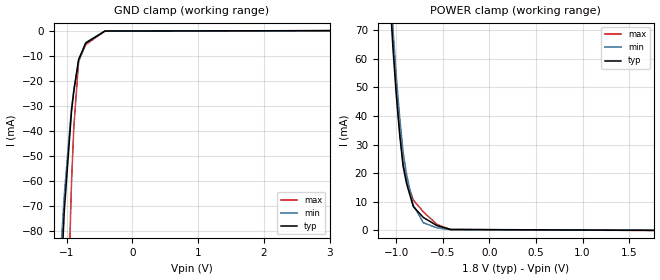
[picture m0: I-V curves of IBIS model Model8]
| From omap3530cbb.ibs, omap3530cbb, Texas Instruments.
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| Model based on original model for BQ0267CS_7LM
|   Sub model BQ0267CS_7LM_PU_ON_1P8
[model]   Model8
|[Input Load]   PU
|[Output Drive]
|Voltage   1.8V
|Mode   INPUT
Model_type   Input
Polarity   Non-Inverting
Vinl =  0.6615
Vinh =  1.2285
C_comp   1.666797p   1.351222p   1.845128p
[Model Spec]
Vinl   0.6615   0.6615   0.6615
Vinh   1.2285   1.2285   1.2285
[Temperature Range]   25   125   -40
[Voltage Range]   1.8   1.62   1.89
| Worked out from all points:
|   GND clamp passes 1 mA (typ) near -0.54 V on its own axis
|   POWER clamp passes 1 mA (typ) near -0.52 V on its own axis
[POWER_clamp]
-1.8V     610.1mA    624.3mA    666.8mA
-1.073V   84.13mA    90.54mA    90.67mA
-1.036V   63.78mA    70.41mA    67.93mA
-1V       47.17mA    53.82mA    49.6mA
-963.6mV  33.4mA     39.47mA    34.78mA
-927.3mV  22.45mA    27.38mA    23.45mA
-890.9mV  16.43mA    19.66mA    17.55mA
-818.2mV  8.267mA    8.667mA    10.56mA
-709.1mV  4.388mA    2.558mA    6.369mA
-563.6mV  1.554mA    772.7uA    1.972mA
-418.2mV  215.4uA    146.1uA    178uA
1.764V    -104.5uA   -51.64uA   -154uA
[GND_clamp]
-1.8V     -588mA     -437.3mA   -1.301A
-1.291V   -227.1mA   -178.9mA   -507.6mA
-1.255V   -202.5mA   -161.3mA   -452.9mA
-1.218V   -178.6mA   -144.2mA   -399.5mA
-1.182V   -155.1mA   -127.4mA   -347.1mA
-1.036V   -71.85mA   -65.55mA   -162.7mA
-927.3mV  -32.54mA   -31.18mA   -61.36mA
-890.9mV  -24.07mA   -23.7mA    -38.46mA
-818.2mV  -11.47mA   -12.29mA   -12.17mA
-709.1mV  -4.95mA    -4.761mA   -5.595mA
-418.2mV  -185.4uA   -235.3uA   -193.6uA
3.6V      0A         0A         0A
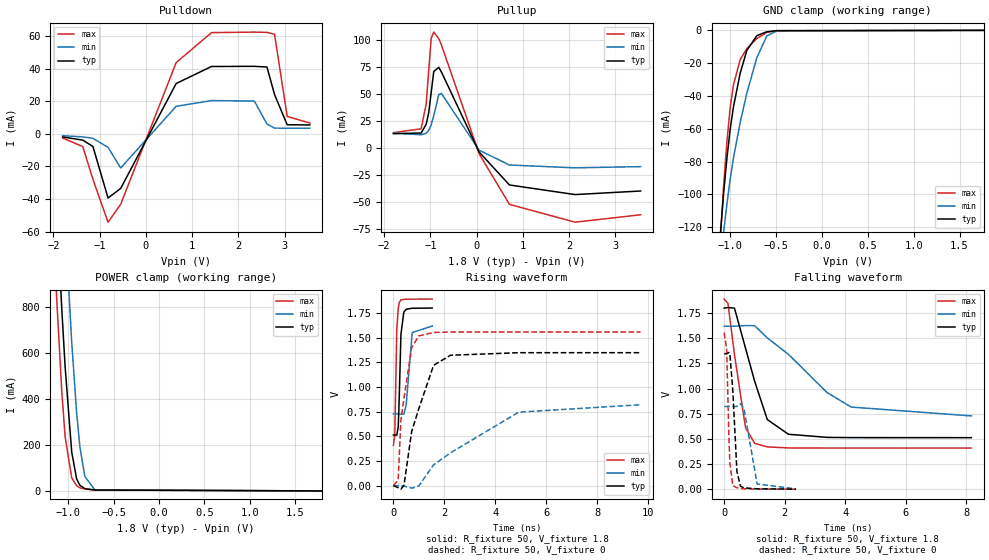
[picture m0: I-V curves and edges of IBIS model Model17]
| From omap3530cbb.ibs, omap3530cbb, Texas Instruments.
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| Model based on original model for BQ0253CS_7LM
|   Sub model BQ0253CS_7LM_PU_ON_1P8
[model]   Model17
|[Input Load]   PU
|[Output Drive]
|Voltage   1.8V
|Mode   I/O
Model_type   I/O
Polarity   Non-Inverting
Enable   Active-Low
Vinl =  0.63
Vinh =  1.17
Cref =  15.0000pF
Rref =  100.0000M
Vref =  0V
Vmeas =  0.9
C_comp   0.8825327p   0.7587673p   1.039339p
[Model Spec]
Vinl   0.63   0.567   0.6615
Vinh   1.17   1.053   1.2285
[Temperature Range]   25   125   -40
[Voltage Range]   1.8   1.62   1.89
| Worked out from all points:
|   slope of the pulldown table from 0 to 0.27 V, typ, clamps not added: 18.2 ohm
|   slope of the pullup table from 0 to 0.27 V, typ, clamps not added: 15.1 ohm
|   GND clamp passes 1 mA (typ) near -0.61 V on its own axis
|   POWER clamp passes 1 mA (typ) near -0.57 V on its own axis
|   rising waveform, R_fixture 50, V_fixture 1.8: 20-80 % time 80.7ps typ, 139ps min, 64.5ps max; typ from 0.513 V to 1.8 V
|   rising waveform, R_fixture 50, V_fixture 0: 20-80 % time 779ps typ, 2.51ns min, 382ps max; typ from 0.001 V to 1.35 V
|   falling waveform, R_fixture 50, V_fixture 1.8: 20-80 % time 756ps typ, 1.98ns min, 422ps max; typ from 1.8 V to 0.513 V
|   falling waveform, R_fixture 50, V_fixture 0: 20-80 % time 127ps typ, 249ps min, 81.5ps max; typ from 1.35 V to 0.002 V
[POWER_clamp]
-1.8V     7.03A      7.477A     6.772A
-1.182V   1.672A     2.34A      1.267A
-1.164V   1.518A     2.189A     1.114A
-1.127V   1.216A     1.889A     820.5mA
-1.073V   791.2mA    1.448A     431.2mA
-1.036V   538.2mA    1.164A     234.6mA
-963.6mV  169mA      647.7mA    57.34mA
-909.1mV  52.04mA    338.7mA    22.18mA
-872.7mV  24.24mA    189.9mA    13.43mA
-818.2mV  9.923mA    62.63mA    8.573mA
-709.1mV  3.896mA    5.034mA    3.819mA
1.8V      4.691nA    3.144nA    7.835nA
[Pulldown]
-1.8V     -1.896mA   -1.14mA    -2.549mA
-1.364V   -3.858mA   -1.868mA   -7.811mA
-1.145V   -7.758mA   -2.749mA   -27.9mA
-818.2mV  -39.37mA   -8.281mA   -54.21mA
-545.5mV  -33.5mA    -20.95mA   -43.25mA
654.5mV   30.89mA    16.9mA     43.69mA
1.418V    41.32mA    20.41mA    62.11mA
2.345V    41.43mA    20.12mA    62.44mA
2.618V    40.99mA    5.968mA    62.24mA
2.782V    24.07mA    3.525mA    61.09mA
3.055V    5.586mA    3.449mA    10.68mA
3.545V    5.467mA    3.446mA    6.63mA
[Pullup]
-1.8V     13mA       13.47mA    13.94mA
-1.2V     13.58mA    11.97mA    17.52mA
-1.091V   21.69mA    13.4mA     40.45mA
-1.036V   32.56mA    16.02mA    72.07mA
-981.8mV  51.55mA    21.35mA    101.5mA
-927.3mV  70.65mA    29.73mA    107.1mA
-818.2mV  74.4mA     49.19mA    101mA
-763.6mV  70.3mA     50.34mA    95.36mA
54.55mV   -4.056mA   -2.362mA   -5.695mA
709.1mV   -34.52mA   -16.04mA   -52.48mA
2.127V    -43.43mA   -18.65mA   -69.01mA
3.545V    -40.12mA   -17.52mA   -62.13mA
[GND_clamp]
-1.8V     -750.7mA   -623.3mA   -941.3mA
-1.109V   -125.7mA   -143.5mA   -129.9mA
-1.073V   -100.4mA   -123.9mA   -96.49mA
-1.036V   -78.3mA    -106.2mA   -68.25mA
-1V       -60.36mA   -90.76mA   -47.12mA
-963.6mV  -46.51mA   -77.61mA   -33.16mA
-890.9mV  -26.17mA   -56.18mA   -17.83mA
-818.2mV  -12.21mA   -38.34mA   -11.05mA
-709.1mV  -3.258mA   -16.62mA   -4.998mA
-600mV    -826.9uA   -3.389mA   -1.229mA
-490.9mV  -188.1uA   -312.3uA   -227.9uA
1.764V    -5.54uA    14.06uA    -26.2uA
[Ramp]
dV/dt_f  0.7815445/0.7631672n  0.5419933/2.008219n   0.9031261/0.4265498n
dV/dt_r  0.8331463/0.779493n   0.5086906/2.537851n   0.965152/0.3828609n
R_load = 50
[Rising Waveform]
R_fixture = 50
V_fixture = 1.8
V_fixture_min = 1.62
V_fixture_max = 1.89
0s        513.1mV    725.9mV    409.7mV
54ps      513.1mV    725.9mV    512.8mV
132ps     512.2mV    726.3mV    1.585V
190ps     595.1mV    726.5mV    1.791V
230ps     901.3mV    726.1mV    1.855V
296ps     1.533V     723.6mV    1.882V
408ps     1.756V     725.4mV    1.887V
500ps     1.787V     814.5mV    1.888V
738ps     1.797V     1.551V     1.889V
1.522ns   1.799V     1.617V     1.89V
[Rising Waveform]
R_fixture = 50
V_fixture = 0
V_fixture_min = 0
V_fixture_max = 0
0s        1.238mV    776.6uV    1.504mV
188ps     -19.74mV   915.1uV    59.45mV
294ps     -34.6mV    1.085mV    667.6mV
416ps     6.055mV    -4.004mV   885.6mV
716ps     547.3mV    -24.5mV    1.398V
996ps     779.5mV    -2.2mV     1.517V
1.576ns   1.219V     211.1mV    1.552V
2.238ns   1.321V     332.9mV    1.556V
4.914ns   1.347V     744.8mV    1.556V
9.702ns   1.347V     819.9mV    1.556V
[Falling Waveform]
R_fixture = 50
V_fixture = 1.8
V_fixture_min = 1.62
V_fixture_max = 1.89
0s        1.8V       1.62V      1.89V
126ps     1.806V     1.62V      1.846V
340ps     1.8V       1.62V      1.34V
706ps     1.402V     1.627V     612.1mV
1.008ns   1.073V     1.626V     457.3mV
1.426ns   693.1mV    1.504V     421.6mV
2.124ns   547mV      1.341V     411.2mV
3.402ns   516.1mV    961.5mV    409.7mV
4.2ns     513.8mV    817.1mV    409.7mV
8.174ns   513.1mV    729.2mV    409.7mV
[Falling Waveform]
R_fixture = 50
V_fixture = 0
V_fixture_min = 0
V_fixture_max = 0
0s        1.347V     823.1mV    1.556V
82ps      1.347V     823.1mV    1.396V
156ps     1.36V      822.5mV    517.3mV
188ps     1.349V     822.3mV    263.5mV
286ps     981.6mV    821.7mV    36.79mV
422ps     177mV      824.2mV    14.81mV
538ps     32.12mV    851mV      10.26mV
654ps     14.22mV    803.7mV    5.479mV
1.09ns    5.212mV    53.26mV    2.809mV
2.376ns   1.916mV    4.022mV    1.588mV
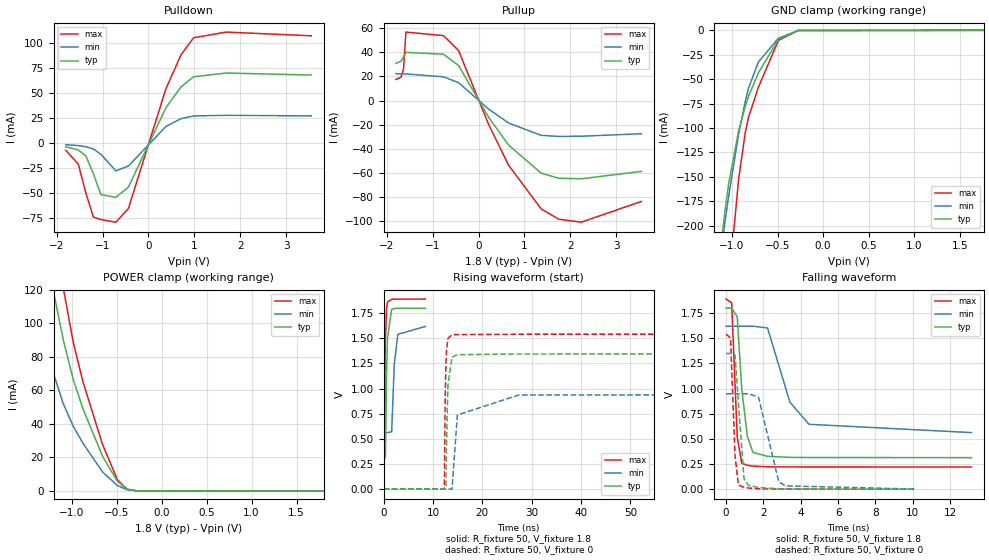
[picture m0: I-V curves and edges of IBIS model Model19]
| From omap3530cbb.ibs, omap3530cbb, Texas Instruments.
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| Model based on original model for BQ0447S_7LM
|   Sub model BQ0447S_7LM_OPEN_1P8
[model]   Model19
|[Input Load]   PI
|[Output Drive]
|Voltage   1.8V
|Mode   I/O
Model_type   I/O
Polarity   Non-Inverting
Enable   Active-Low
Vinl =  0.63
Vinh =  1.17
Cref =  15.0000pF
Rref =  100.0000M
Vref =  0V
Vmeas =  0.9
C_comp   14.35822p   13.74686p   15.2046p
[Model Spec]
Vinl   0.63   0.567   0.6615
Vinh   1.17   1.053   1.2285
[Temperature Range]   25   125   -40
[Voltage Range]   1.8   1.62   1.89
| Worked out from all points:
|   slope of the pulldown table from 0 to 0.27 V, typ, clamps not added: 10.4 ohm
|   slope of the pullup table from 0 to 0.27 V, typ, clamps not added: 16.1 ohm
|   GND clamp passes 1 mA (typ) near -0.34 V on its own axis
|   POWER clamp passes 1 mA (typ) near -0.38 V on its own axis
|   rising waveform, R_fixture 50, V_fixture 1.8: 20-80 % time 309ps typ, 590ps min, 201ps max; typ from 0.313 V to 1.8 V
|   rising waveform, R_fixture 50, V_fixture 0: 20-80 % time 387ps typ, 2ns min, 239ps max; typ from 0 V to 1.35 V
|   falling waveform, R_fixture 50, V_fixture 1.8: 20-80 % time 397ps typ, 1.15ns min, 221ps max; typ from 1.8 V to 0.314 V
|   falling waveform, R_fixture 50, V_fixture 0: 20-80 % time 255ps typ, 657ps min, 169ps max; typ from 1.35 V to 0 V
[POWER_clamp]
-1.8V     303.4mA    203.4mA    381.1mA
-1.455V   193.8mA    122.8mA    249.4mA
-1.218V   124mA      73.42mA    164.2mA
-1.2V     118.8mA    69.94mA    157.8mA
-1.091V   89.97mA    51.91mA    120.8mA
-981.8mV  66.58mA    38.67mA    88.78mA
-872.7mV  48.89mA    28.38mA    65mA
-654.5mV  20.58mA    11.27mA    27.57mA
-490.9mV  5.761mA    3.217mA    6.81mA
-381.8mV  1.056mA    692uA      943.7uA
-272.7mV  66.9uA     68.21uA    41.35uA
1.8V      41.6nA     285.5nA    43.96nA
[Pulldown]
-1.8V     -4.045mA   -1.989mA   -7.643mA
-1.527V   -7.297mA   -2.932mA   -21.5mA
-1.364V   -13.13mA   -4.035mA   -50.14mA
-1.2V     -30.92mA   -6.24mA    -74.18mA
-1.036V   -51.82mA   -11.63mA   -76.77mA
-709.1mV  -54.59mA   -28.19mA   -79.4mA
-436.4mV  -44.39mA   -23.3mA    -65.68mA
381.8mV   34.97mA    16.22mA    53.99mA
709.1mV   55.7mA     23.96mA    87.7mA
981.8mV   65.76mA    26.68mA    104.7mA
1.691V    69.52mA    27.31mA    110.4mA
3.545V    67.51mA    26.7mA     106.7mA
[Pullup]
-1.8V     30.85mA    22.33mA    17.55mA
-1.691V   32.55mA    22.17mA    19.38mA
-1.636V   35.97mA    22.14mA    25.89mA
-1.582V   40.02mA    22.12mA    56.78mA
-763.6mV  38.44mA    19.71mA    53.84mA
-436.4mV  29.17mA    14.9mA     41.51mA
218.2mV   -13.71mA   -6.987mA   -19.71mA
654.5mV   -36.87mA   -18.56mA   -53.56mA
1.364V    -60.07mA   -28.75mA   -89.7mA
1.745V    -64.29mA   -29.65mA   -98.22mA
2.236V    -64.75mA   -29.49mA   -100.7mA
3.545V    -58.6mA    -27.43mA   -83.51mA
[GND_clamp]
-1.8V     -901.6mA   -764.7mA   -1.495A
-1.218V   -303.4mA   -297.3mA   -491.3mA
-1.182V   -270.3mA   -270.3mA   -440.1mA
-1.073V   -181.9mA   -193.4mA   -303mA
-1.036V   -156.9mA   -169.4mA   -261mA
-927.3mV  -102.9mA   -106mA     -152.4mA
-854.5mV  -77.94mA   -72.99mA   -104.8mA
-818.2mV  -67.27mA   -58.97mA   -88.77mA
-709.1mV  -43.37mA   -32.32mA   -57.99mA
-490.9mV  -9.476mA   -8.137mA   -10.47mA
-272.7mV  -130.2uA   -230.7uA   -82.15uA
1.764V    38.64nA    3.228uA    40.69nA
[Ramp]
dV/dt_f  0.8932329/0.3927921n  0.6370527/1.142175n   1.003819/0.2201368n
dV/dt_r  0.8096603/0.3800384n  0.5693228/0.801983n   0.925524/0.2383233n
R_load = 50
[Rising Waveform]
R_fixture = 50
V_fixture = 1.8
V_fixture_min = 1.62
V_fixture_max = 1.89
0s        313.1mV    560.9mV    220.7mV
120ps     313.2mV    560.9mV    226mV
300ps     313.1mV    560.9mV    1.32V
360ps     325.6mV    560.9mV    1.496V
600ps     1.17V      560.9mV    1.804V
780ps     1.505V     561.3mV    1.86V
1.62ns    1.787V     570.8mV    1.888V
2.16ns    1.796V     1.245V     1.889V
2.88ns    1.798V     1.539V     1.889V
8.46ns    1.799V     1.618V     1.89V
[Rising Waveform]
R_fixture = 50
V_fixture = 0
V_fixture_min = 0
V_fixture_max = 0
0s        1.543uV    7.401uV    396.5nV
12.3ns    2.326uV    13.75uV    288.1uV
12.48ns   -202.4uV   2.405uV    919.6mV
12.6ns    6.814mV    378.7nV    1.212V
12.72ns   383.6mV    -312.2nV   1.363V
13.02ns   1.037V     -18.87nV   1.498V
13.86ns   1.312V     -464.2uV   1.535V
14.94ns   1.337V     737.2mV    1.537V
27.36ns   1.344V     935.8mV    1.54V
312.7ns   1.348V     947.2mV    1.542V
[Falling Waveform]
R_fixture = 50
V_fixture = 1.8
V_fixture_min = 1.62
V_fixture_max = 1.89
0s        1.8V       1.62V      1.89V
300ps     1.8V       1.62V      1.853V
600ps     1.713V     1.62V      516.8mV
840ps     998.3mV    1.62V      258.1mV
1.14ns    524.9mV    1.62V      237.8mV
1.44ns    365.5mV    1.62V      229.8mV
2.22ns    326.8mV    1.603V     222.7mV
3.42ns    316.4mV    864.5mV    221.3mV
4.44ns    314.7mV    645.1mV    221.1mV
13.14ns   313.5mV    562.5mV    220.8mV
[Falling Waveform]
R_fixture = 50
V_fixture = 0
V_fixture_min = 0
V_fixture_max = 0
0s        1.349V     948.8mV    1.542V
240ps     1.349V     948.8mV    1.502V
480ps     1.335V     948.8mV    335.9mV
660ps     865.2mV    948.8mV    41.54mV
960ps     106.4mV    948.8mV    18.6mV
1.2ns     37.13mV    948.8mV    11.53mV
1.74ns    16.21mV    915.2mV    3.72mV
2.82ns    3.973mV    74.69mV    761.3uV
3.18ns    2.678mV    32.99mV    597.1uV
10.08ns   456.3uV    1.645mV    168.5uV
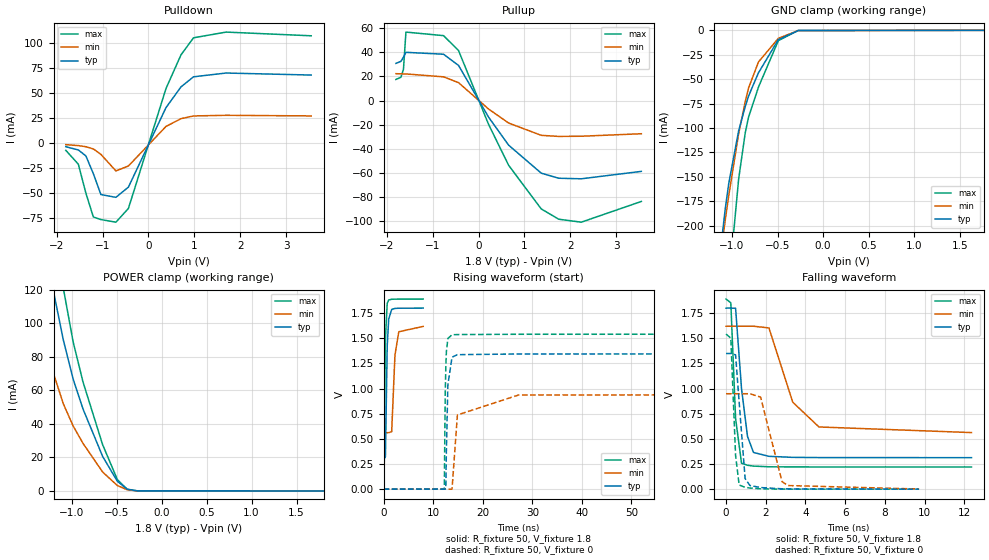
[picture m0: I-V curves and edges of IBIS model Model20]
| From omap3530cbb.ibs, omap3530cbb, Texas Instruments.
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| Model based on original model for BQ0447S_7LM
|   Sub model BQ0447S_7LM_PU_1P8
[model]   Model20
|[Input Load]   PU
|[Output Drive]
|Voltage   1.8V
|Mode   I/O
Model_type   I/O
Polarity   Non-Inverting
Enable   Active-Low
Vinl =  0.63
Vinh =  1.17
Cref =  15.0000pF
Rref =  100.0000M
Vref =  0V
Vmeas =  0.9
C_comp   14.35822p   13.74686p   15.2046p
[Model Spec]
Vinl   0.63   0.567   0.6615
Vinh   1.17   1.053   1.2285
[Temperature Range]   25   125   -40
[Voltage Range]   1.8   1.62   1.89
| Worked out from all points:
|   slope of the pulldown table from 0 to 0.27 V, typ, clamps not added: 10.4 ohm
|   slope of the pullup table from 0 to 0.27 V, typ, clamps not added: 16.1 ohm
|   GND clamp passes 1 mA (typ) near -0.34 V on its own axis
|   POWER clamp passes 1 mA (typ) near -0.38 V on its own axis
|   rising waveform, R_fixture 50, V_fixture 1.8: 20-80 % time 309ps typ, 590ps min, 201ps max; typ from 0.313 V to 1.8 V
|   rising waveform, R_fixture 50, V_fixture 0: 20-80 % time 387ps typ, 1.98ns min, 239ps max; typ from 0 V to 1.35 V
|   falling waveform, R_fixture 50, V_fixture 1.8: 20-80 % time 397ps typ, 1.15ns min, 221ps max; typ from 1.8 V to 0.314 V
|   falling waveform, R_fixture 50, V_fixture 0: 20-80 % time 255ps typ, 657ps min, 169ps max; typ from 1.35 V to 0.001 V
[POWER_clamp]
-1.8V     303.4mA    203.4mA    381.1mA
-1.455V   193.8mA    122.8mA    249.4mA
-1.218V   124mA      73.42mA    164.3mA
-1.2V     118.8mA    69.94mA    157.8mA
-1.091V   89.98mA    51.91mA    120.8mA
-981.8mV  66.59mA    38.68mA    88.78mA
-872.7mV  48.89mA    28.38mA    65.01mA
-654.5mV  20.58mA    11.28mA    27.58mA
-490.9mV  5.766mA    3.22mA     6.817mA
-381.8mV  1.06mA     694.7uA    950.1uA
-272.7mV  70.48uA    70.45uA    46.36uA
1.8V      41.6nA     285.5nA    43.96nA
[Pulldown]
-1.8V     -4.045mA   -1.989mA   -7.643mA
-1.527V   -7.297mA   -2.932mA   -21.5mA
-1.364V   -13.13mA   -4.035mA   -50.14mA
-1.2V     -30.92mA   -6.24mA    -74.18mA
-1.036V   -51.82mA   -11.63mA   -76.77mA
-709.1mV  -54.59mA   -28.19mA   -79.4mA
-436.4mV  -44.39mA   -23.3mA    -65.68mA
381.8mV   34.97mA    16.22mA    53.99mA
709.1mV   55.7mA     23.96mA    87.7mA
981.8mV   65.76mA    26.68mA    104.7mA
1.691V    69.52mA    27.31mA    110.4mA
3.545V    67.51mA    26.7mA     106.7mA
[Pullup]
-1.8V     30.85mA    22.33mA    17.55mA
-1.691V   32.55mA    22.17mA    19.38mA
-1.636V   35.97mA    22.14mA    25.89mA
-1.582V   40.02mA    22.12mA    56.78mA
-763.6mV  38.44mA    19.71mA    53.84mA
-436.4mV  29.17mA    14.9mA     41.51mA
218.2mV   -13.71mA   -6.987mA   -19.71mA
654.5mV   -36.87mA   -18.56mA   -53.56mA
1.364V    -60.07mA   -28.75mA   -89.7mA
1.745V    -64.29mA   -29.65mA   -98.22mA
2.236V    -64.75mA   -29.49mA   -100.7mA
3.545V    -58.6mA    -27.43mA   -83.51mA
[GND_clamp]
-1.8V     -901.6mA   -764.7mA   -1.495A
-1.218V   -303.4mA   -297.3mA   -491.3mA
-1.182V   -270.3mA   -270.3mA   -440.1mA
-1.073V   -181.9mA   -193.4mA   -303mA
-1.036V   -156.9mA   -169.4mA   -261mA
-927.3mV  -102.9mA   -106mA     -152.4mA
-854.5mV  -77.95mA   -73mA      -104.8mA
-818.2mV  -67.28mA   -58.97mA   -88.79mA
-709.1mV  -43.39mA   -32.33mA   -58.03mA
-490.9mV  -9.507mA   -8.155mA   -10.51mA
-272.7mV  -158.5uA   -247.6uA   -122.8uA
1.764V    -449.8nA   4.475uA    -2.299uA
[Ramp]
dV/dt_f  0.8931151/0.3926831n  0.6369209/1.141517n   1.003703/0.2200896n
dV/dt_r  0.8095912/0.3796781n  0.5692851/0.8011317n  0.9254441/0.2381167n
R_load = 50
[Rising Waveform]
R_fixture = 50
V_fixture = 1.8
V_fixture_min = 1.62
V_fixture_max = 1.89
0s        313.3mV    561.1mV    220.9mV
120ps     313.4mV    561.1mV    226.2mV
300ps     313.3mV    561.1mV    1.32V
360ps     325.8mV    561.1mV    1.497V
720ps     1.426V     561.3mV    1.848V
1.02ns    1.691V     561.8mV    1.881V
1.62ns    1.787V     571.1mV    1.888V
2.28ns    1.797V     1.333V     1.889V
3.06ns    1.799V     1.565V     1.89V
7.98ns    1.8V       1.618V     1.89V
[Rising Waveform]
R_fixture = 50
V_fixture = 0
V_fixture_min = 0
V_fixture_max = 0
0s        195.4uV    205.4uV    195.8uV
12.24ns   196.3uV    211.7uV    487.3uV
12.42ns   -7.22uV    200.4uV    919.9mV
12.54ns   7.055mV    198.4uV    1.213V
12.66ns   384mV      197.7uV    1.364V
12.96ns   1.037V     198.1uV    1.498V
13.8ns    1.312V     -256.4uV   1.535V
14.88ns   1.337V     737.5mV    1.537V
27.24ns   1.344V     936.2mV    1.54V
311.4ns   1.348V     947.3mV    1.542V
[Falling Waveform]
R_fixture = 50
V_fixture = 1.8
V_fixture_min = 1.62
V_fixture_max = 1.89
0s        1.8V       1.62V      1.89V
240ps     1.8V       1.62V      1.853V
480ps     1.799V     1.62V      703.3mV
780ps     998.3mV    1.62V      258.1mV
1.08ns    524.9mV    1.62V      237.8mV
1.38ns    365.5mV    1.62V      229.8mV
2.16ns    326.8mV    1.603V     222.7mV
3.36ns    316.4mV    864.5mV    221.4mV
4.68ns    314.5mV    618.6mV    221.2mV
12.36ns   313.6mV    562.8mV    221mV
[Falling Waveform]
R_fixture = 50
V_fixture = 0
V_fixture_min = 0
V_fixture_max = 0
0s        1.349V     948.9mV    1.542V
240ps     1.349V     948.9mV    1.502V
480ps     1.335V     948.9mV    336mV
660ps     865.3mV    948.9mV    41.58mV
960ps     106.4mV    948.9mV    18.64mV
1.2ns     37.18mV    949mV      11.57mV
1.74ns    16.26mV    915.3mV    3.756mV
2.82ns    4.019mV    74.83mV    809.8uV
3.12ns    2.894mV    36.22mV    671.9uV
9.72ns    531.6uV    1.851mV    321.7uV
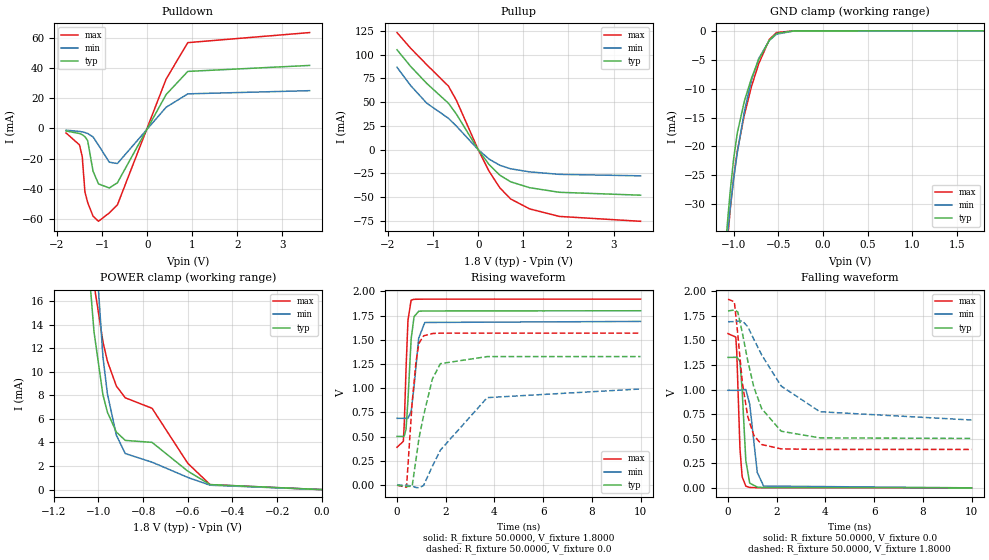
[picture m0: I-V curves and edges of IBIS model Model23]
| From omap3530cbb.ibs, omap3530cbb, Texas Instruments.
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| Model based on original model for DSIPHY_7LM
|   Sub model gpio_dx
[model]   Model23
|[Input Load]
|[Output Drive]
|Voltage   1.8000V
|Mode   I/O
Model_type I/O
Polarity   Non-Inverting
Enable   Active-High
Vinl =   0.4000V
Vinh =   1.4000V
Cref = 20pF
Rref = 10k
Vref = 0V
Vmeas =  0.9
C_comp   1.5000pF   1.4000pF   1.6000pF
[Temperature Range]   25.0000   0.1100k   -40.0000
[Voltage Range]   1.8000V   1.6900V   1.9200V
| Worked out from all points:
|   slope of the pulldown table from 0 to 0.27 V, typ, clamps not added: 17.9 ohm
|   slope of the pullup table from 0 to 0.27 V, typ, clamps not added: 15.7 ohm
|   GND clamp passes 1 mA (typ) near -0.57 V on its own axis
|   POWER clamp passes 1 mA (typ) near -0.56 V on its own axis
|   rising waveform, R_fixture 50.0000, V_fixture 1.8000: 20-80 % time 163ps typ, 221ps min, 126ps max; typ from 0.503 V to 1.8 V
|   rising waveform, R_fixture 50.0000, V_fixture 0.0: 20-80 % time 630ps typ, 1.6ns min, 293ps max; typ from 0 V to 1.33 V
|   falling waveform, R_fixture 50.0000, V_fixture 0.0: 20-80 % time 170ps typ, 253ps min, 133ps max; typ from 1.33 V to 0 V
|   falling waveform, R_fixture 50.0000, V_fixture 1.8000: 20-80 % time 854ps typ, 1.71ns min, 457ps max; typ from 1.8 V to 0.503 V
[Pulldown]
-1.8V     -1.734mA   -1.194mA   -3.023mA
-1.5V     -3.408mA   -2.016mA   -10.94mA
-1.44V    -4.211mA   -2.33mA    -18.71mA
-1.38V    -5.513mA   -2.754mA   -42.05mA
-1.32V    -8.079mA   -3.352mA   -48.98mA
-1.2V     -28.36mA   -5.657mA   -58.07mA
-1.08V    -36.71mA   -11.09mA   -61.44mA
-840mV    -39.42mA   -22.37mA   -55.89mA
-660mV    -35.96mA   -23.23mA   -50.58mA
420mV     22.37mA    13.96mA    32.59mA
900mV     37.65mA    22.81mA    56.68mA
3.6V      41.6mA     24.92mA    63.33mA
[Pullup]
-1.8V     105.2mA    86.79mA    123.3mA
-1.5V     87.8mA     67.64mA    106.9mA
-1.14V    69.72mA    48.95mA    89.46mA
-660mV    48.93mA    33.07mA    66.96mA
-480mV    37.21mA    24.7mA     51.68mA
0V        22.99pA    8.01pA     54.91pA
240mV     -15.57mA   -9.825mA   -22.62mA
480mV     -26.83mA   -16.42mA   -40.16mA
720mV     -33.8mA    -20.11mA   -51.88mA
1.14V     -40mA      -23.35mA   -62.31mA
1.8V      -44.84mA   -25.95mA   -70.25mA
3.6V      -47.9mA    -27.51mA   -75.38mA
[GND_clamp]
-1.8V     -216.5mA   -190.9mA   -249.2mA
-1.08V    -34.96mA   -36.72mA   -38.27mA
-1.04V    -27.87mA   -30.76mA   -31.13mA
-1V       -22.05mA   -25.57mA   -25.33mA
-960mV    -17.69mA   -21.1mA    -20.85mA
-880mV    -12.12mA   -13.91mA   -14.5mA
-800mV    -8.161mA   -8.492mA   -9.579mA
-720mV    -5.008mA   -4.788mA   -5.698mA
-600mV    -1.609mA   -1.645mA   -1.473mA
-520mV    -446.3uA   -578.6uA   -291.1uA
-320mV    -4.076uA   -10.07uA   -2.168uA
1.8V      482.7pA    75.41nA    410.7pA
[POWER_clamp]
-1.8V     3.651A     2.994A     4.508A
-1.06V    25.18mA    47.72mA    25.53mA
-1.04V    18.08mA    32.73mA    20.93mA
-1.02V    13.37mA    22.64mA    17.43mA
-980mV    8.037mA    11.24mA    12.54mA
-960mV    6.565mA    8.132mA    10.89mA
-920mV    4.881mA    4.616mA    8.785mA
-880mV    4.173mA    3.057mA    7.785mA
-760mV    4.006mA    2.326mA    6.898mA
-600mV    1.566mA    1.033mA    2.23mA
-500mV    425.7uA    372.5uA    422.6uA
0V        482.7pA    2.598nA    445.9pA
[Ramp]
dV/dt_r  0.7964/0.6301n   0.5955/1.6028n   0.9415/0.2930n
dV/dt_f  0.7783/0.8543n   0.5998/1.7093n   0.9175/0.4566n
R_load = 50.0000
[Rising Waveform]
R_fixture= 50.0000
V_fixture= 1.8000
V_fixture_min= 1.6900
V_fixture_max= 1.9200
0s        502.8mV    689.6mV    390.9mV
260.3ps   502.8mV    689.8mV    452.1mV
300.3ps   508mV      689.6mV    645.6mV
370.4ps   576.8mV    689mV      1.198V
450.5ps   881.7mV    691mV      1.704V
580.6ps   1.509V     760.8mV    1.91V
700.7ps   1.739V     1.018V     1.918V
890.9ps   1.795V     1.517V     1.919V
1.141ns   1.798V     1.679V     1.92V
10ns      1.8V       1.69V      1.92V
[Rising Waveform]
R_fixture= 50.0000
V_fixture= 0.0
V_fixture_min= 0.0
V_fixture_max= 0.0
0s        162.7nV    203.1nV    258.6nV
390.4ps   -13.48mV   93.09uV    -22.31mV
620.6ps   -12.01mV   -10.83mV   847.9mV
780.8ps   267.2mV    -24.52mV   1.275V
900.9ps   482.7mV    -28.13mV   1.464V
1.091ns   718.5mV    -3.95mV    1.541V
1.452ns   1.096V     195.1mV    1.565V
1.782ns   1.254V     361.7mV    1.569V
3.704ns   1.327V     903.4mV    1.569V
10ns      1.327V     992.5mV    1.569V
[Falling Waveform]
R_fixture= 50.0000
V_fixture= 0.0
V_fixture_min= 0.0
V_fixture_max= 0.0
0s        1.327V     992.4mV    1.569V
320.3ps   1.328V     992.3mV    1.534V
360.4ps   1.331V     992.2mV    1.374V
490.5ps   1.288V     992.6mV    401.2mV
580.6ps   991.1mV    996.4mV    113.9mV
730.7ps   278.8mV    1.001V     16.99mV
890.9ps   48.43mV    852.1mV    4.604mV
1.201ns   7.343mV    156.8mV    1.183mV
1.462ns   3.098mV    18.3mV     767.3uV
10ns      193.7nV    17.53uV    271.1nV
[Falling Waveform]
R_fixture= 50.0000
V_fixture= 1.8000
V_fixture_min= 1.6900
V_fixture_max= 1.9200
0s        1.8V       1.69V      1.92V
260.3ps   1.809V     1.691V     1.892V
400.4ps   1.79V      1.696V     1.564V
590.6ps   1.574V     1.698V     1.065V
810.8ps   1.293V     1.64V      724.2mV
1.061ns   1.024V     1.511V     534mV
1.381ns   806.8mV    1.353V     441mV
2.182ns   576.1mV    1.036V     396.5mV
3.774ns   508.4mV    774.3mV    391mV
10ns      502.9mV    690.3mV    390.9mV
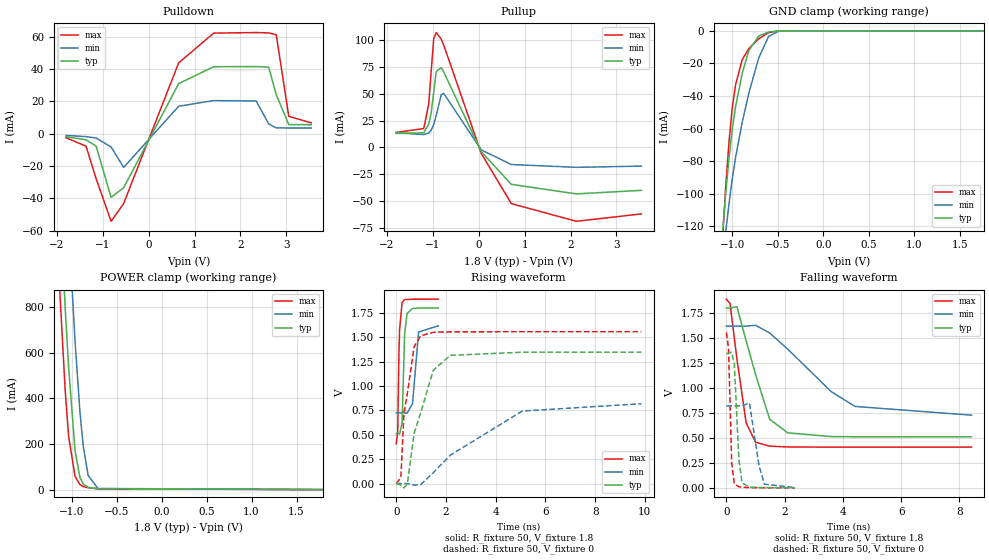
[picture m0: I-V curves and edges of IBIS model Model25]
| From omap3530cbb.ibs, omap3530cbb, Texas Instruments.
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| Model based on original model for BQ0230CS_7LM
|   Sub model 0230CS_PD_PU_OFF_1P8
[model]   Model25
|[Input Load]   PI
|[Output Drive]
|Voltage   1.8V
|Mode   I/O
Model_type   I/O
Polarity   Non-Inverting
Enable   Active-Low
Vinl =  0.63
Vinh =  1.17
Cref =  15.0000pF
Rref =  100.0000M
Vref =  0V
Vmeas =  0.9
C_comp   0.6926437p   0.6051649p   0.8002447p
[Model Spec]
Vinl   0.63   0.567   0.6615
Vinh   1.17   1.053   1.2285
[Temperature Range]   25   125   -40
[Voltage Range]   1.8   1.62   1.89
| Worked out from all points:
|   slope of the pulldown table from 0 to 0.27 V, typ, clamps not added: 18.2 ohm
|   slope of the pullup table from 0 to 0.27 V, typ, clamps not added: 15.1 ohm
|   GND clamp passes 1 mA (typ) near -0.62 V on its own axis
|   POWER clamp passes 1 mA (typ) near -0.57 V on its own axis
|   rising waveform, R_fixture 50, V_fixture 1.8: 20-80 % time 82.2ps typ, 143ps min, 65.7ps max; typ from 0.511 V to 1.8 V
|   rising waveform, R_fixture 50, V_fixture 0: 20-80 % time 779ps typ, 2.51ns min, 383ps max; typ from 0 V to 1.35 V
|   falling waveform, R_fixture 50, V_fixture 1.8: 20-80 % time 759ps typ, 1.98ns min, 424ps max; typ from 1.8 V to 0.511 V
|   falling waveform, R_fixture 50, V_fixture 0: 20-80 % time 127ps typ, 250ps min, 81.6ps max; typ from 1.35 V to 0.001 V
[POWER_clamp]
-1.8V     7.03A      7.477A     6.772A
-1.182V   1.672A     2.34A      1.267A
-1.164V   1.518A     2.189A     1.114A
-1.127V   1.216A     1.889A     820.4mA
-1.073V   791.2mA    1.448A     431.2mA
-1.036V   538.2mA    1.164A     234.5mA
-963.6mV  168.9mA    647.7mA    57.19mA
-909.1mV  51.95mA    338.6mA    22.02mA
-872.7mV  24.13mA    189.8mA    13.26mA
-818.2mV  9.807mA    62.59mA    8.409mA
-709.1mV  3.786mA    4.97mA     3.667mA
1.8V      5.595nA    3.536nA    9.29nA
[Pulldown]
-1.8V     -1.896mA   -1.14mA    -2.549mA
-1.364V   -3.858mA   -1.868mA   -7.811mA
-1.145V   -7.758mA   -2.749mA   -27.9mA
-818.2mV  -39.37mA   -8.28mA    -54.21mA
-545.5mV  -33.5mA    -20.95mA   -43.25mA
654.5mV   30.89mA    16.9mA     43.69mA
1.418V    41.32mA    20.41mA    62.11mA
2.345V    41.43mA    20.12mA    62.44mA
2.618V    40.99mA    5.968mA    62.24mA
2.782V    24.07mA    3.525mA    61.09mA
3.055V    5.586mA    3.449mA    10.68mA
3.545V    5.467mA    3.446mA    6.63mA
[Pullup]
-1.8V     13mA       13.47mA    13.94mA
-1.2V     13.58mA    11.97mA    17.52mA
-1.091V   21.69mA    13.4mA     40.44mA
-1.036V   32.56mA    16.02mA    72.05mA
-981.8mV  51.54mA    21.35mA    101.5mA
-927.3mV  70.65mA    29.72mA    107.1mA
-818.2mV  74.4mA     49.19mA    101mA
-763.6mV  70.3mA     50.34mA    95.36mA
54.55mV   -4.056mA   -2.362mA   -5.695mA
709.1mV   -34.52mA   -16.04mA   -52.48mA
2.127V    -43.43mA   -18.65mA   -69.01mA
3.545V    -40.12mA   -17.52mA   -62.13mA
[GND_clamp]
-1.8V     -750.6mA   -623.3mA   -941.3mA
-1.109V   -125.7mA   -143.5mA   -129.8mA
-1.073V   -100.3mA   -123.9mA   -96.46mA
-1.036V   -78.28mA   -106.2mA   -68.22mA
-1V       -60.33mA   -90.75mA   -47.08mA
-963.6mV  -46.48mA   -77.6mA    -33.12mA
-890.9mV  -26.13mA   -56.16mA   -17.76mA
-818.2mV  -12.14mA   -38.32mA   -10.94mA
-709.1mV  -3.178mA   -16.6mA    -4.875mA
-600mV    -741.1uA   -3.353mA   -1.097mA
-490.9mV  -93.82uA   -272.7uA   -81.21uA
1.764V    4.634nA    31.23nA    5.135nA
[Ramp]
dV/dt_f  0.7838245/0.7674859n  0.5431736/2.016907n   0.9061657/0.4292492n
dV/dt_r  0.8345672/0.7801617n  0.5086817/2.534964n   0.9673251/0.3833999n
R_load = 50
[Rising Waveform]
R_fixture = 50
V_fixture = 1.8
V_fixture_min = 1.62
V_fixture_max = 1.89
0s        511.5mV    724.7mV    407.9mV
60ps      511.3mV    724.7mV    531.4mV
108ps     510mV      724.8mV    1.321V
136ps     508.7mV    724.9mV    1.578V
236ps     618.3mV    724.9mV    1.854V
338ps     1.532V     723.9mV    1.885V
436ps     1.745V     721.3mV    1.887V
656ps     1.794V     818.7mV    1.889V
900ps     1.798V     1.553V     1.889V
1.696ns   1.799V     1.617V     1.89V
[Rising Waveform]
R_fixture = 50
V_fixture = 0
V_fixture_min = 0
V_fixture_max = 0
0s        196.5nV    87.63nV    427nV
188ps     -15.38mV   13.61uV    60.91mV
310ps     -44.05mV   178.9uV    718.9mV
450ps     -633.4uV   -16.84uV   925.9mV
720ps     514.1mV    -15.78mV   1.402V
980ps     722.8mV    -11.92mV   1.514V
1.49ns    1.161V     111.4mV    1.55V
2.18ns    1.314V     291.6mV    1.555V
5.07ns    1.346V     743mV      1.556V
9.858ns   1.346V     818.1mV    1.556V
[Falling Waveform]
R_fixture = 50
V_fixture = 1.8
V_fixture_min = 1.62
V_fixture_max = 1.89
0s        1.8V       1.62V      1.89V
126ps     1.801V     1.62V      1.847V
364ps     1.814V     1.62V      1.29V
680ps     1.473V     1.62V      651.7mV
1.004ns   1.135V     1.628V     456.9mV
1.488ns   687.2mV    1.551V     417.9mV
2.108ns   550.8mV    1.389V     409.6mV
3.596ns   513.8mV    964.4mV    407.9mV
4.416ns   512mV      815.5mV    407.9mV
8.414ns   511.5mV    727.9mV    407.9mV
[Falling Waveform]
R_fixture = 50
V_fixture = 0
V_fixture_min = 0
V_fixture_max = 0
0s        1.346V     821.4mV    1.556V
74ps      1.346V     821.5mV    1.405V
184ps     1.358V     820.9mV    248.3mV
274ps     1.241V     820.5mV    39.94mV
432ps     279.8mV    820.2mV    10.59mV
540ps     50.71mV    821.8mV    7.009mV
794ps     8.258mV    850.4mV    2.213mV
1.12ns    3.426mV    224.2mV    1.167mV
1.306ns   2.172mV    36.38mV    771.4uV
2.354ns   681.5uV    3.249mV    81.16uV
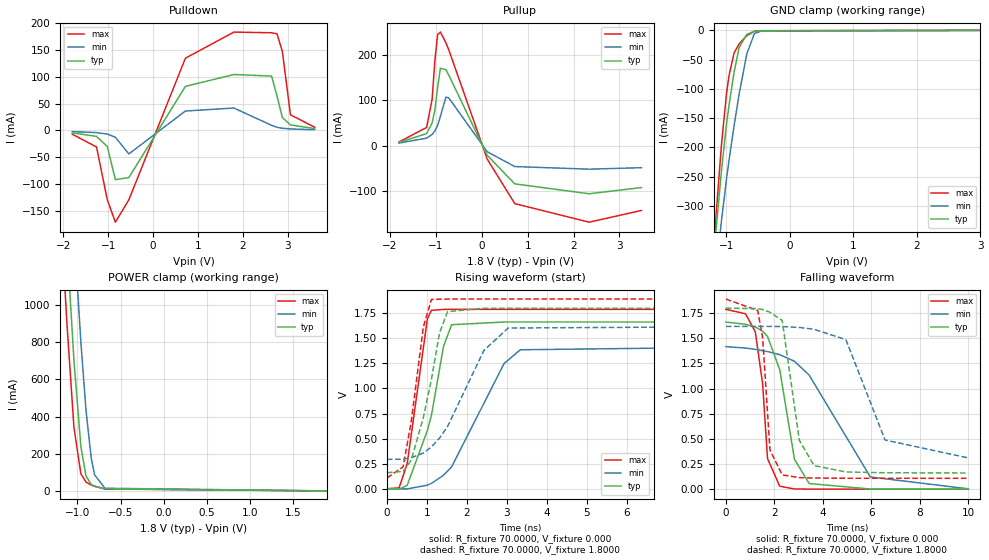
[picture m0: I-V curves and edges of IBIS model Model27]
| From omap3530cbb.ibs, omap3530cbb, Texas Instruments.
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| Model based on original model for BQ0246S_7LM
|   Sub model BQ0246S_7LM_NOM
[model]   Model27
|[Input Load]
|[Output Drive]
|Voltage   1.8000V
|Mode   I/O
Model_type   I/O
Polarity   Non-Inverting
Enable   Active-Low
Vinl =   0.6615V
Vinh =   1.0530V
Vmeas =   0.9000V
Cref =  15.0000pF
Rref =  70.0000
Vref =  0.000V
C_comp   27.0699pF   15.4565pF   39.2456pF
[Temperature Range]   25.0000   0.1250k   -40.0000
[Voltage Range]   1.8000V   1.6200V   1.8900V
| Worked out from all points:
|   slope of the pulldown table from 0 to 0.27 V, typ, clamps not added: 7.19 ohm
|   slope of the pullup table from 0 to 0.27 V, typ, clamps not added: 6.32 ohm
|   GND clamp passes 1 mA (typ) near -0.50 V on its own axis
|   POWER clamp passes 1 mA (typ) near -0.42 V on its own axis
|   rising waveform, R_fixture 70.0000, V_fixture 0.000: 20-80 % time 536ps typ, 1.05ns min, 366ps max; typ from 0.003 V to 1.66 V
|   rising waveform, R_fixture 70.0000, V_fixture 1.8000: 20-80 % time 503ps typ, 982ps min, 357ps max; typ from 0.162 V to 1.8 V
|   falling waveform, R_fixture 70.0000, V_fixture 0.000: 20-80 % time 746ps typ, 1.96ns min, 378ps max; typ from 1.66 V to 0.003 V
|   falling waveform, R_fixture 70.0000, V_fixture 1.8000: 20-80 % time 487ps typ, 1.12ns min, 284ps max; typ from 1.8 V to 0.162 V
[Pulldown]
-1.8V     -4.445mA   -2.126mA   -6.996mA
-1.26V    -11.04mA   -4.025mA   -30.71mA
-1.02V    -29.82mA   -6.736mA   -128.8mA
-840mV    -91.43mA   -12.6mA    -170.6mA
-540mV    -87.67mA   -43.72mA   -129mA
720mV     81.92mA    36.14mA    134.3mA
1.8V      104mA      41.7mA     182.9mA
2.64V     101.1mA    9.526mA    181.6mA
2.76V     64.23mA    5.807mA    179.9mA
2.88V     23.98mA    4.088mA    146.8mA
3.06V     10.27mA    2.794mA    29.14mA
3.6V      3.524mA    1.407mA    5.962mA
[Pullup]
-1.8V     7.604mA    6.269mA    8.75mA
-1.2V     27.23mA    17.12mA    40.67mA
-1.08V    50.58mA    25.44mA    102.7mA
-1.02V    79.05mA    32.97mA    188.3mA
-960mV    129.4mA    45.19mA    245mA
-900mV    170.8mA    65.19mA    250.2mA
-780mV    167.6mA    107mA      226.8mA
-720mV    156.1mA    105.8mA    211.9mA
120mV     -20.62mA   -12.72mA   -29.04mA
720mV     -83.38mA   -45.32mA   -126.8mA
2.34V     -105.1mA   -51.09mA   -167.6mA
3.48V     -91.45mA   -47.78mA   -141.8mA
[GND_clamp]
-1.8V     -1.222A    -1.152A    -1.363A
-1.2V     -387.2mA   -450.4mA   -371mA
-1.16V    -336.3mA   -407.6mA   -310.2mA
-1.08V    -241mA     -326.5mA   -197.1mA
-1V       -161.1mA   -254.5mA   -108.6mA
-960mV    -128mA     -222.2mA   -77.4mA
-880mV    -71.17mA   -162.8mA   -38.58mA
-800mV    -29.24mA   -108.5mA   -23mA
-680mV    -6.808mA   -40.29mA   -9.038mA
-560mV    -1.734mA   -5.52mA    -1.729mA
-440mV    -712.8uA   -867uA     -705.7uA
3.6V      0A         0A         0A
[POWER_clamp]
-1.8V     7.644A     8.363A     7.23A
-1.2V     2.005A     2.755A     1.56A
-1.18V    1.83A      2.579A     1.387A
-1.14V    1.487A     2.231A     1.051A
-1.12V    1.32A      2.059A     889.9mA
-1.04V    701.3mA    1.398A     341.4mA
-960mV    239.2mA    801mA      92.52mA
-900mV    79.9mA     431.2mA    47.25mA
-840mV    34.57mA    177mA      31.56mA
-800mV    24.75mA    85.38mA    25.1mA
-680mV    11.25mA    14.42mA    10.49mA
1.89V     0A         0A         0A
[Ramp]
dV/dt_r   0.9945/0.5312n   0.8467/1.0443n   1.0703/0.3627n
dV/dt_f   0.9812/0.4824n   0.7828/1.1180n   1.0669/0.2906n
R_load = 70.0000
[Rising Waveform]
R_fixture = 70.0000
V_fixture = 0.000
V_fixture_min = 0.000
V_fixture_max = 0.000
0s        2.514mV    4.296mV    1.746mV
303ps     -1.766mV   1.683mV    11.58mV
505.1ps   35.5mV     1.032mV    249.7mV
1.01ns    581.3mV    37.7mV     1.689V
1.111ns   730.1mV    55.93mV    1.776V
1.414ns   1.419V     136.3mV    1.785V
1.616ns   1.633V     220mV      1.786V
2.929ns   1.66V      1.248V     1.786V
3.333ns   1.66V      1.384V     1.786V
10ns      1.66V      1.415V     1.786V
[Rising Waveform]
R_fixture = 70.0000
V_fixture = 1.8000
V_fixture_min = 1.6200
V_fixture_max = 1.8900
0s        161.6mV    294.1mV    109.7mV
404ps     175mV      296.4mV    220.6mV
606.1ps   285.9mV    310.2mV    669.2mV
909.1ps   710.5mV    357.9mV    1.61V
1.111ns   1.089V     418.2mV    1.884V
1.313ns   1.55V      505.9mV    1.887V
1.515ns   1.763V     621.5mV    1.888V
2.424ns   1.797V     1.378V     1.888V
3.03ns    1.797V     1.6V       1.888V
10ns      1.797V     1.616V     1.888V
[Falling Waveform]
R_fixture = 70.0000
V_fixture = 0.000
V_fixture_min = 0.000
V_fixture_max = 0.000
0s        1.66V      1.416V     1.786V
808.1ps   1.638V     1.402V     1.742V
1.212ns   1.611V     1.389V     1.564V
1.515ns   1.569V     1.376V     1.048V
1.717ns   1.518V     1.367V     305.3mV
2.222ns   1.186V     1.336V     31mV
2.828ns   299.3mV    1.271V     3.702mV
3.434ns   57.85mV    1.134V     2.641mV
5.96ns    3.238mV    122.8mV    2.003mV
10ns      2.828mV    5.304mV    1.945mV
[Falling Waveform]
R_fixture = 70.0000
V_fixture = 1.8000
V_fixture_min = 1.6200
V_fixture_max = 1.8900
0s        1.798V     1.617V     1.888V
1.313ns   1.793V     1.617V     1.774V
1.515ns   1.784V     1.617V     1.506V
1.818ns   1.757V     1.617V     390mV
2.323ns   1.675V     1.615V     143.5mV
3.03ns    486mV      1.606V     116mV
3.636ns   236.3mV    1.588V     112.5mV
4.949ns   172.7mV    1.486V     110.5mV
6.566ns   164.9mV    489.6mV    110mV
10ns      162.2mV    311.9mV    109.9mV
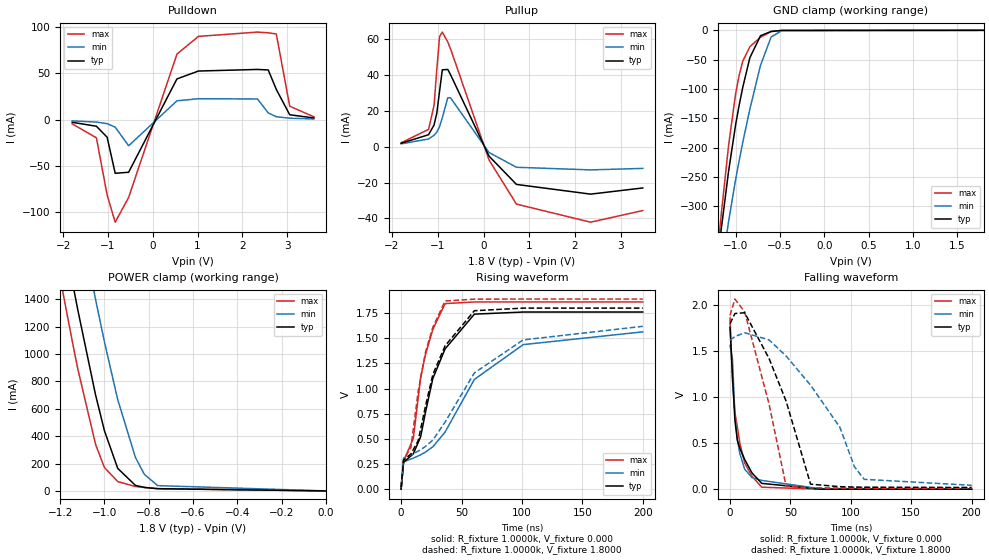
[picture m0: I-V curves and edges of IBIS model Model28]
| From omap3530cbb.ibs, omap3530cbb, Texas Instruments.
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| Model based on original model for BQ0246S_7LM
|   Sub model BQ0246S_7LM_I2C_2
[model]   Model28
|[Input Load]
|[Output Drive] HIGHC
|Voltage   1.8000V
|Mode   I/O
Model_type   I/O
Polarity   Non-Inverting
Enable   Active-Low
Vinl =   0.6615V
Vinh =   1.0530V
Vmeas =   0.9000V
Cref =  15.0000pF
Rref =  70.0000
Vref =  1.800V
C_comp   27.0699pF   15.4565pF   39.2456pF
[Temperature Range]   25.0000   0.1250k   -40.0000
[Voltage Range]   1.8000V   1.6200V   1.8900V
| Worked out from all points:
|   slope of the pulldown table from 0 to 0.27 V, typ, clamps not added: 11 ohm
|   slope of the pullup table from 0 to 0.27 V, typ, clamps not added: 25 ohm
|   GND clamp passes 1 mA (typ) near -0.56 V on its own axis
|   POWER clamp passes 1 mA (typ) near -0.50 V on its own axis
|   rising waveform, R_fixture 1.0000k, V_fixture 0.000: 20-80 % time 26.9ns typ, 65.3ns min, 16.2ns max; typ from 0 V to 1.76 V
|   rising waveform, R_fixture 1.0000k, V_fixture 1.8000: 20-80 % time 27.5ns typ, 66.1ns min, 16.4ns max; typ from 0.018 V to 1.8 V
|   falling waveform, R_fixture 1.0000k, V_fixture 0.000: 20-80 % time 9.81ns typ, 7.03ns min, 8.99ns max; typ from 1.76 V to 0 V
|   falling waveform, R_fixture 1.0000k, V_fixture 1.8000: 20-80 % time 28ns typ, 44.1ns min, 19.5ns max; typ from 1.8 V to 0.018 V
[Pulldown]
-1.8V     -2.87mA    -1.375mA   -4.529mA
-1.26V    -7.103mA   -2.596mA   -19.64mA
-1.02V    -19mA      -4.333mA   -81.54mA
-840mV    -58mA      -8.066mA   -110.9mA
-540mV    -56.9mA    -28.26mA   -84.16mA
540mV     44.06mA    20.37mA    70.88mA
1.02V     52.59mA    22.64mA    90.07mA
2.34V     54.31mA    22.37mA    94.71mA
2.58V     53.76mA    7.273mA    93.96mA
2.76V     32.74mA    3.19mA     92.69mA
3.06V     5.312mA    1.538mA    14.56mA
3.6V      1.833mA    776uA      3.052mA
[Pullup]
-1.8V     1.906mA    1.589mA    2.175mA
-1.2V     6.671mA    4.3mA      9.634mA
-1.08V    12.15mA    6.353mA    23.09mA
-1.02V    18.75mA    8.198mA    43.29mA
-960mV    31mA       11.19mA    61.33mA
-900mV    42.83mA    16.12mA    63.84mA
-780mV    43.01mA    27.29mA    58.27mA
-720mV    40.08mA    27.21mA    54.48mA
120mV     -5.231mA   -3.221mA   -7.396mA
720mV     -21.02mA   -11.47mA   -31.99mA
2.34V     -26.43mA   -12.93mA   -42.06mA
3.48V     -22.99mA   -12.1mA    -35.57mA
[GND_clamp]
-1.8V     -1.221A    -1.151A    -1.363A
-1.2V     -386.5mA   -449.7mA   -370.2mA
-1.16V    -335.5mA   -406.8mA   -309.4mA
-1.08V    -240.2mA   -325.8mA   -196.3mA
-1V       -160.3mA   -253.8mA   -107.7mA
-960mV    -127.1mA   -221.5mA   -76.33mA
-920mV    -97.28mA   -191.1mA   -52.71mA
-840mV    -46.78mA   -134.3mA   -27.94mA
-720mV    -9.253mA   -59.82mA   -11.79mA
-600mV    -1.888mA   -11.35mA   -2.27mA
-480mV    -137.6uA   -650.4uA   -84.11uA
1.8V      510.5nA    3.198uA    487.6nA
[POWER_clamp]
-1.8V     7.644A     8.363A     7.23A
-1.2V     2.004A     2.755A     1.56A
-1.18V    1.829A     2.578A     1.386A
-1.14V    1.486A     2.23A      1.05A
-1.12V    1.32A      2.059A     889mA
-1.04V    700.2mA    1.398A     339.6mA
-1V       439.3mA    1.088A     170.8mA
-940mV    164.6mA    666.7mA    68.12mA
-860mV    40.26mA    244.2mA    32.16mA
-820mV    25.74mA    121.5mA    25.05mA
-760mV    16.31mA    38.76mA    16.75mA
0V        510.5nA    462.5nA    537.3nA
[Ramp]
dV/dt_r   1.0568/26.6090n   0.9382/64.6276n   1.1166/15.9899n
dV/dt_f   1.0691/27.7433n   0.9467/45.2102n   1.1268/19.2673n
R_load = 1.0000k
[Rising Waveform]
R_fixture = 1.0000k
V_fixture = 0.000
V_fixture_min = 0.000
V_fixture_max = 0.000
0s        4.661uV    8.557uV    3.644uV
2.02ns    267.4mV    271.7mV    277.7mV
10.1ns    351.6mV    308.8mV    505.1mV
16.16ns   521.1mV    342mV      1.113V
20.2ns    767mV      369.2mV    1.341V
26.26ns   1.101V     421.8mV    1.589V
36.36ns   1.394V     567.6mV    1.845V
60.61ns   1.74V      1.091V     1.861V
101ns     1.761V     1.437V     1.861V
200ns     1.761V     1.564V     1.861V
[Rising Waveform]
R_fixture = 1.0000k
V_fixture = 1.8000
V_fixture_min = 1.6200
V_fixture_max = 1.8900
0s        17.75mV    32.74mV    11.97mV
2.02ns    288mV      309.1mV    291.7mV
8.081ns   348.6mV    341.3mV    414.2mV
14.14ns   483.4mV    378mV      974mV
20.2ns    827.5mV    424.6mV    1.364V
26.26ns   1.14V      488.1mV    1.609V
36.36ns   1.425V     666.4mV    1.871V
60.61ns   1.774V     1.156V     1.889V
101ns     1.8V       1.484V     1.89V
200ns     1.8V       1.619V     1.89V
[Falling Waveform]
R_fixture = 1.0000k
V_fixture = 0.000
V_fixture_min = 0.000
V_fixture_max = 0.000
0s        1.761V     1.564V     1.861V
2.02ns    1.239V     1.411V     1.186V
4.04ns    749.2mV    809.4mV    831.9mV
6.061ns   532.5mV    539.1mV    676.5mV
8.081ns   445.6mV    389.2mV    501.8mV
12.12ns   322.7mV    217.4mV    284.9mV
18.18ns   176.4mV    126.4mV    140.6mV
26.26ns   63.04mV    95.09mV    21.16mV
74.75ns   227.6uV    4.43mV     65.06uV
200ns     11.7uV     85.92uV    4.143uV
[Falling Waveform]
R_fixture = 1.0000k
V_fixture = 1.8000
V_fixture_min = 1.6200
V_fixture_max = 1.8900
0s        1.8V       1.62V      1.89V
4.04ns    1.911V     1.661V     2.068V
12.12ns   1.919V     1.701V     1.929V
32.32ns   1.421V     1.624V     925.4mV
46.46ns   955.7mV    1.448V     31.89mV
66.67ns   54.47mV    1.131V     14.94mV
90.91ns   26.84mV    673.8mV    12.69mV
103ns     22.93mV    242.9mV    12.34mV
111.1ns   21.66mV    106.9mV    12.23mV
200ns     18.14mV    42.11mV    11.98mV
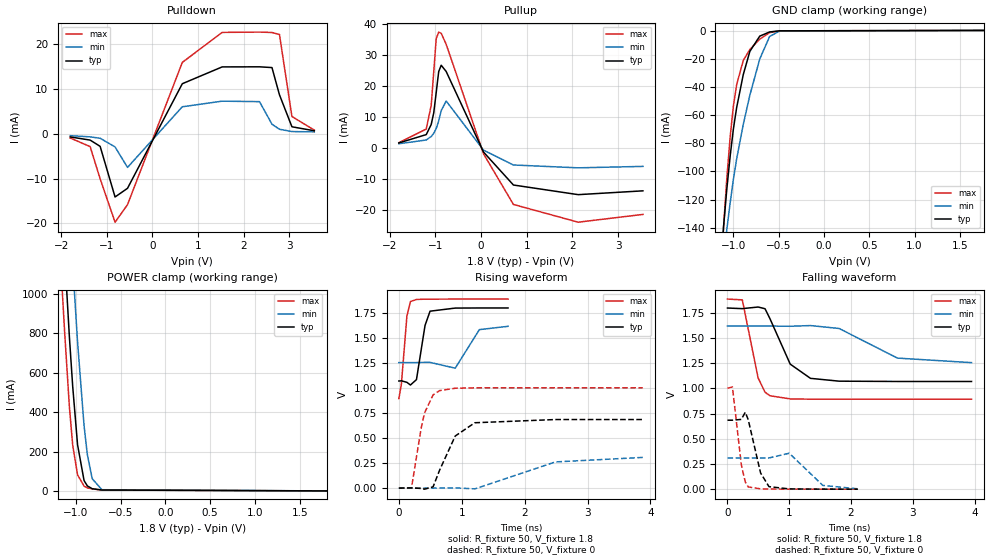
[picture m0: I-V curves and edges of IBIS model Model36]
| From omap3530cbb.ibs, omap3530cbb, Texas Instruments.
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| Model based on original model for BQOMAPPROGIOCSHYFBPB_7LM
|   Sub model MODE11_PD_ON_1P8
[model]   Model36
|[Input Load]   PD
|[Output Drive] DS11
|Voltage   1.8V
|Mode   I/O
Model_type   I/O
Polarity   Non-Inverting
Enable   Active-Low
Vinl =  0.63
Vinh =  1.17
Cref =  15.0000pF
Rref =  100.0000M
Vref =  0V
Vmeas =  0.9
C_comp   0.8864943p   0.7714798p   1.034566p
[Model Spec]
Vinl   0.63   0.567   0.6615
Vinh   1.17   1.053   1.2285
[Temperature Range]   25   125   -40
[Voltage Range]   1.8   1.62   1.89
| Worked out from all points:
|   slope of the pulldown table from 0 to 0.27 V, typ, clamps not added: 50.2 ohm
|   slope of the pullup table from 0 to 0.27 V, typ, clamps not added: 43.2 ohm
|   GND clamp passes 1 mA (typ) near -0.60 V on its own axis
|   POWER clamp passes 1 mA (typ) near -0.55 V on its own axis
|   rising waveform, R_fixture 50, V_fixture 1.8: 20-80 % time 108ps typ, 168ps min, 75.7ps max; typ from 1.07 V to 1.8 V
|   rising waveform, R_fixture 50, V_fixture 0: 20-80 % time 310ps typ, 715ps min, 175ps max; typ from 0 V to 0.684 V
|   falling waveform, R_fixture 50, V_fixture 1.8: 20-80 % time 338ps typ, 637ps min, 197ps max; typ from 1.8 V to 1.07 V
|   falling waveform, R_fixture 50, V_fixture 0: 20-80 % time 159ps typ, 301ps min, 108ps max; typ from 0.684 V to 0 V
[POWER_clamp]
-1.8V     7.429A     8.065A     7.064A
-1.182V   1.663A     2.35A      1.259A
-1.164V   1.508A     2.193A     1.106A
-1.127V   1.206A     1.883A     813.3mA
-1.073V   782.1mA    1.435A     426.3mA
-1.036V   530.7mA    1.15A      232.5mA
-981.8mV  234.7mA    756.3mA    81.79mA
-909.1mV  52.86mA    331.4mA    24.54mA
-872.7mV  25.66mA    185.5mA    15.5mA
-818.2mV  11.27mA    62mA       10.15mA
-709.1mV  4.611mA    6.166mA    4.556mA
1.8V      101uA      43.59uA    177.4uA
[Pulldown]
-1.8V     -685.7uA   -406.8uA   -929.8uA
-1.364V   -1.393mA   -666uA     -2.846mA
-1.145V   -2.793mA   -979uA     -10.06mA
-818.2mV  -14.12mA   -2.924mA   -19.76mA
-545.5mV  -12.18mA   -7.506mA   -15.84mA
654.5mV   11.22mA    6.067mA    15.99mA
1.527V    14.98mA    7.316mA    22.7mA
2.345V    15mA       7.209mA    22.77mA
2.618V    14.83mA    2.157mA    22.68mA
2.782V    8.739mA    1.031mA    22.24mA
3.055V    1.587mA    518.5uA    3.885mA
3.545V    690.3uA    442.8uA    842.1uA
[Pullup]
-1.8V     1.529mA    1.269mA    1.629mA
-1.2V     4.224mA    2.481mA    6.016mA
-1.091V   7.505mA    3.622mA    13.74mA
-1.036V   11.25mA    4.62mA     24.52mA
-981.8mV  17.83mA    6.179mA    35.2mA
-927.3mV  24.58mA    8.646mA    37.31mA
-872.7mV  26.61mA    11.97mA    36.93mA
-763.6mV  24.59mA    15.07mA    33.37mA
54.55mV   -1.419mA   -813.7uA   -1.994mA
709.1mV   -12.05mA   -5.587mA   -18.32mA
2.127V    -15.16mA   -6.505mA   -24.05mA
3.545V    -13.93mA   -6.04mA    -21.54mA
[GND_clamp]
-1.8V     -794.1mA   -670.5mA   -980.8mA
-1.109V   -139.6mA   -162.6mA   -140.1mA
-1.073V   -112.8mA   -141.5mA   -105.3mA
-1.036V   -89.25mA   -122.4mA   -75.78mA
-1V       -69.85mA   -105.6mA   -53.4mA
-963.6mV  -54.51mA   -90.99mA   -38.26mA
-890.9mV  -31.22mA   -66.62mA   -21.22mA
-818.2mV  -14.77mA   -45.88mA   -13.44mA
-709.1mV  -3.952mA   -20.19mA   -6.104mA
-600mV    -982.9uA   -4.198mA   -1.476mA
-490.9mV  -187.6uA   -374.7uA   -215.1uA
1.764V    101uA      43.71uA    177.3uA
[Ramp]
dV/dt_f  0.4432279/0.3387982n  0.2228411/0.6536895n  0.6043236/0.198385n
dV/dt_r  0.4197515/0.3104211n  0.1915724/0.7412433n  0.6120512/0.1755736n
R_load = 50
[Rising Waveform]
R_fixture = 50
V_fixture = 1.8
V_fixture_min = 1.62
V_fixture_max = 1.89
0s        1.069V     1.253V     892.8mV
40ps      1.071V     1.253V     1.037V
128ps     1.056V     1.253V     1.717V
184ps     1.029V     1.253V     1.862V
280ps     1.083V     1.253V     1.883V
416ps     1.623V     1.255V     1.886V
496ps     1.766V     1.255V     1.886V
896ps     1.797V     1.197V     1.887V
1.28ns    1.798V     1.582V     1.887V
1.736ns   1.798V     1.615V     1.887V
[Rising Waveform]
R_fixture = 50
V_fixture = 0
V_fixture_min = 0
V_fixture_max = 0
0s        443.1nV    254.2nV    1.018uV
200ps     2.658mV    4.996uV    -1.265mV
352ps     -3.306mV   -17.1uV    590.4mV
408ps     -10.49mV   -112.7uV   749.9mV
544ps     12.59mV    -66.89uV   930.3mV
648ps     179.5mV    595.1uV    973.4mV
896ps     519.9mV    2.326mV    996.8mV
1.208ns   652.5mV    -7.743mV   1.001V
2.488ns   684.4mV    261.4mV    1.001V
3.88ns    684.4mV    306.5mV    1.001V
[Falling Waveform]
R_fixture = 50
V_fixture = 1.8
V_fixture_min = 1.62
V_fixture_max = 1.89
0s        1.798V     1.619V     1.887V
240ps     1.792V     1.619V     1.879V
496ps     1.808V     1.619V     1.104V
608ps     1.791V     1.619V     962.4mV
688ps     1.692V     1.619V     927.4mV
1.016ns   1.241V     1.617V     895.9mV
1.344ns   1.1V       1.624V     893.2mV
1.808ns   1.072V     1.595V     892.9mV
2.752ns   1.069V     1.301V     892.9mV
3.952ns   1.069V     1.256V     892.9mV
[Falling Waveform]
R_fixture = 50
V_fixture = 0
V_fixture_min = 0
V_fixture_max = 0
0s        684.4mV    309.9mV    1.001V
80ps      684.5mV    309.9mV    1.015V
224ps     692.5mV    309.9mV    243mV
288ps     763.2mV    309.9mV    71.42mV
336ps     689.8mV    309.9mV    22.47mV
536ps     160.9mV    309.9mV    3.049mV
672ps     24.91mV    309.9mV    1.199mV
1ns       2.59mV     356.5mV    113.2uV
1.544ns   194.2uV    37.33mV    3.891uV
2.112ns   20.04uV    3.285mV    1.303uV
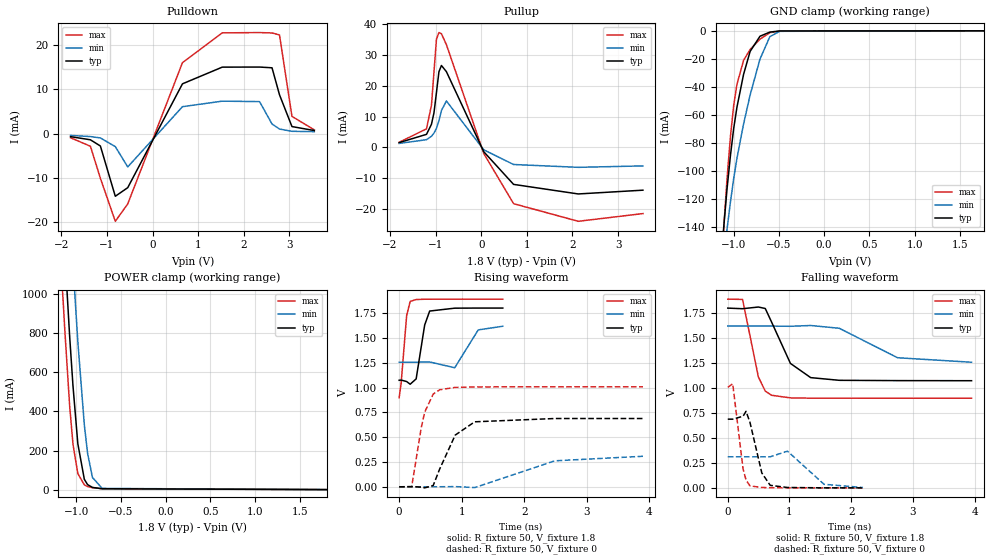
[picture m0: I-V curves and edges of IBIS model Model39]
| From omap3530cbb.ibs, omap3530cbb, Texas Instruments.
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| Model based on original model for BQOMAPPROGIOCSHYFBPB_7LM
|   Sub model MODE11_PU_PD_OFF_1P8
[model]   Model39
|[Input Load]   PI
|[Output Drive] DS11
|Voltage   1.8V
|Mode   I/O
Model_type   I/O
Polarity   Non-Inverting
Enable   Active-Low
Vinl =  0.63
Vinh =  1.17
Cref =  15.0000pF
Rref =  100.0000M
Vref =  0V
Vmeas =  0.9
C_comp   0.8864943p   0.7714798p   1.034566p
[Model Spec]
Vinl   0.63   0.567   0.6615
Vinh   1.17   1.053   1.2285
[Temperature Range]   25   125   -40
[Voltage Range]   1.8   1.62   1.89
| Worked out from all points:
|   slope of the pulldown table from 0 to 0.27 V, typ, clamps not added: 50.2 ohm
|   slope of the pullup table from 0 to 0.27 V, typ, clamps not added: 43.2 ohm
|   GND clamp passes 1 mA (typ) near -0.61 V on its own axis
|   POWER clamp passes 1 mA (typ) near -0.56 V on its own axis
|   rising waveform, R_fixture 50, V_fixture 1.8: 20-80 % time 107ps typ, 167ps min, 75.2ps max; typ from 1.07 V to 1.8 V
|   rising waveform, R_fixture 50, V_fixture 0: 20-80 % time 312ps typ, 718ps min, 176ps max; typ from 0 V to 0.688 V
|   falling waveform, R_fixture 50, V_fixture 1.8: 20-80 % time 338ps typ, 636ps min, 198ps max; typ from 1.8 V to 1.07 V
|   falling waveform, R_fixture 50, V_fixture 0: 20-80 % time 160ps typ, 303ps min, 109ps max; typ from 0.688 V to 0 V
[POWER_clamp]
-1.8V     7.429A     8.065A     7.064A
-1.182V   1.663A     2.35A      1.259A
-1.164V   1.508A     2.193A     1.106A
-1.127V   1.206A     1.883A     813.2mA
-1.073V   782.1mA    1.435A     426.3mA
-1.036V   530.6mA    1.15A      232.4mA
-981.8mV  234.7mA    756.3mA    81.67mA
-909.1mV  52.8mA     331.4mA    24.39mA
-872.7mV  25.58mA    185.5mA    15.34mA
-818.2mV  11.18mA    61.99mA    9.987mA
-709.1mV  4.516mA    6.134mA    4.387mA
1.8V      470.6pA    2.239nA    626.3pA
[Pulldown]
-1.8V     -685.7uA   -406.8uA   -929.8uA
-1.364V   -1.393mA   -666uA     -2.846mA
-1.145V   -2.793mA   -979uA     -10.06mA
-818.2mV  -14.12mA   -2.924mA   -19.76mA
-545.5mV  -12.18mA   -7.506mA   -15.84mA
654.5mV   11.22mA    6.067mA    15.99mA
1.527V    14.98mA    7.316mA    22.7mA
2.345V    15mA       7.209mA    22.77mA
2.618V    14.83mA    2.157mA    22.68mA
2.782V    8.738mA    1.031mA    22.24mA
3.055V    1.587mA    518.5uA    3.885mA
3.545V    690.3uA    442.8uA    842.1uA
[Pullup]
-1.8V     1.529mA    1.269mA    1.629mA
-1.2V     4.224mA    2.481mA    6.016mA
-1.091V   7.504mA    3.622mA    13.74mA
-1.036V   11.25mA    4.62mA     24.52mA
-981.8mV  17.82mA    6.179mA    35.19mA
-927.3mV  24.58mA    8.646mA    37.31mA
-872.7mV  26.61mA    11.97mA    36.93mA
-763.6mV  24.59mA    15.07mA    33.37mA
54.55mV   -1.419mA   -813.6uA   -1.993mA
709.1mV   -12.05mA   -5.587mA   -18.32mA
2.127V    -15.16mA   -6.504mA   -24.05mA
3.545V    -13.93mA   -6.04mA    -21.54mA
[GND_clamp]
-1.8V     -794.1mA   -670.5mA   -980.8mA
-1.109V   -139.6mA   -162.5mA   -140mA
-1.073V   -112.7mA   -141.5mA   -105.3mA
-1.036V   -89.23mA   -122.4mA   -75.75mA
-1V       -69.83mA   -105.6mA   -53.36mA
-963.6mV  -54.49mA   -90.99mA   -38.21mA
-890.9mV  -31.19mA   -66.62mA   -21.14mA
-818.2mV  -14.71mA   -45.88mA   -13.31mA
-709.1mV  -3.87mA    -20.18mA   -5.973mA
-600mV    -903.1uA   -4.176mA   -1.354mA
-490.9mV  -116.3uA   -342.2uA   -105.5uA
1.764V    389.6pA    119.4nA    561.5pA
[Ramp]
dV/dt_f  0.4425488/0.3390115n  0.2223979/0.6529139n  0.6048573/0.1989728n
dV/dt_r  0.4218333/0.3124462n  0.1921807/0.7437925n  0.6155477/0.1770175n
R_load = 50
[Rising Waveform]
R_fixture = 50
V_fixture = 1.8
V_fixture_min = 1.62
V_fixture_max = 1.89
0s        1.073V     1.255V     897.5mV
32ps      1.075V     1.255V     1.043V
120ps     1.06V      1.255V     1.725V
176ps     1.033V     1.255V     1.867V
272ps     1.087V     1.255V     1.886V
408ps     1.629V     1.257V     1.889V
488ps     1.77V      1.257V     1.889V
888ps     1.799V     1.199V     1.89V
1.264ns   1.8V       1.58V      1.89V
1.656ns   1.8V       1.617V     1.89V
[Rising Waveform]
R_fixture = 50
V_fixture = 0
V_fixture_min = 0
V_fixture_max = 0
0s        443.5nV    254.2nV    1.02uV
200ps     2.658mV    4.996uV    -1.27mV
352ps     -3.303mV   -17.1uV    590.8mV
408ps     -10.49mV   -112.7uV   751.1mV
544ps     12.58mV    -66.91uV   933.4mV
648ps     179.4mV    595.1uV    977.5mV
896ps     520.7mV    2.326mV    1.001V
1.208ns   654.7mV    -7.742mV   1.006V
2.488ns   687.8mV    261.8mV    1.007V
3.896ns   687.9mV    307.6mV    1.007V
[Falling Waveform]
R_fixture = 50
V_fixture = 1.8
V_fixture_min = 1.62
V_fixture_max = 1.89
0s        1.8V       1.62V      1.89V
240ps     1.794V     1.62V      1.887V
496ps     1.811V     1.62V      1.111V
608ps     1.796V     1.62V      968.7mV
712ps     1.658V     1.62V      927mV
1.016ns   1.246V     1.618V     901mV
1.344ns   1.104V     1.626V     898.2mV
1.808ns   1.077V     1.598V     897.7mV
2.752ns   1.074V     1.303V     897.6mV
3.952ns   1.073V     1.258V     897.5mV
[Falling Waveform]
R_fixture = 50
V_fixture = 0
V_fixture_min = 0
V_fixture_max = 0
0s        687.9mV    310.9mV    1.007V
80ps      687.9mV    310.9mV    1.043V
248ps     717mV      310.9mV    189.5mV
296ps     766.5mV    310.9mV    79.03mV
360ps     656.2mV    310.9mV    19.71mV
552ps     149.3mV    310.9mV    3.908mV
688ps     25.23mV    310.9mV    1.589mV
968ps     3.717mV    367.6mV    249.8uV
1.56ns    248.8uV    35.99mV    7.4uV
2.192ns   25.33uV    3.303mV    1.275uV
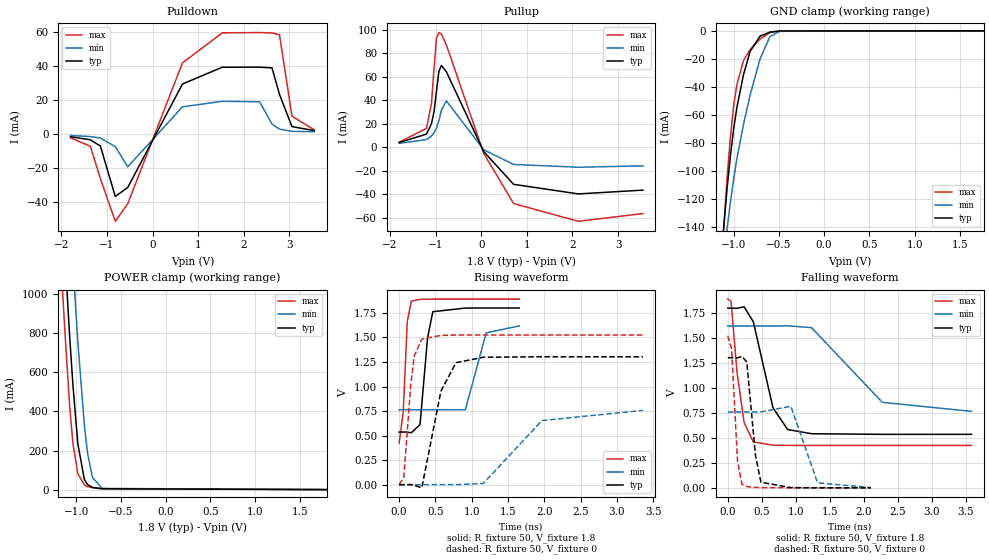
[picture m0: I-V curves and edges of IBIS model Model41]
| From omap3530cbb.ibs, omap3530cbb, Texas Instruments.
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| Model based on original model for BQOMAPPROGIOCSHYFBPB_7LM
|   Sub model MODE01_PU_PD_OFF_1P8
[model]   Model41
|[Input Load]   PI
|[Output Drive] DS01
|Voltage   1.8V
|Mode   I/O
Model_type   I/O
Polarity   Non-Inverting
Enable   Active-Low
Vinl =  0.63
Vinh =  1.17
Cref =  15.0000pF
Rref =  100.0000M
Vref =  0V
Vmeas =  0.9
C_comp   0.8864943p   0.7714798p   1.034566p
[Model Spec]
Vinl   0.63   0.567   0.6615
Vinh   1.17   1.053   1.2285
[Temperature Range]   25   125   -40
[Voltage Range]   1.8   1.62   1.89
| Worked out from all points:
|   slope of the pulldown table from 0 to 0.27 V, typ, clamps not added: 19.3 ohm
|   slope of the pullup table from 0 to 0.27 V, typ, clamps not added: 16.6 ohm
|   GND clamp passes 1 mA (typ) near -0.61 V on its own axis
|   POWER clamp passes 1 mA (typ) near -0.56 V on its own axis
|   rising waveform, R_fixture 50, V_fixture 1.8: 20-80 % time 86.7ps typ, 154ps min, 53.4ps max; typ from 0.536 V to 1.8 V
|   rising waveform, R_fixture 50, V_fixture 0: 20-80 % time 202ps typ, 558ps min, 101ps max; typ from 0 V to 1.3 V
|   falling waveform, R_fixture 50, V_fixture 1.8: 20-80 % time 271ps typ, 742ps min, 144ps max; typ from 1.8 V to 0.536 V
|   falling waveform, R_fixture 50, V_fixture 0: 20-80 % time 104ps typ, 186ps min, 69.1ps max; typ from 1.3 V to 0 V
[POWER_clamp]
-1.8V     7.429A     8.065A     7.064A
-1.182V   1.663A     2.35A      1.259A
-1.164V   1.508A     2.193A     1.106A
-1.127V   1.206A     1.883A     813.2mA
-1.073V   782.1mA    1.435A     426.3mA
-1.036V   530.6mA    1.15A      232.4mA
-981.8mV  234.7mA    756.3mA    81.67mA
-909.1mV  52.8mA     331.4mA    24.39mA
-872.7mV  25.58mA    185.5mA    15.34mA
-818.2mV  11.18mA    61.99mA    9.987mA
-709.1mV  4.516mA    6.134mA    4.387mA
1.8V      470.6pA    2.239nA    626.3pA
[Pulldown]
-1.8V     -1.789mA   -1.059mA   -2.429mA
-1.364V   -3.636mA   -1.733mA   -7.448mA
-1.145V   -7.295mA   -2.547mA   -26.48mA
-818.2mV  -36.98mA   -7.617mA   -51.58mA
-545.5mV  -31.67mA   -19.52mA   -41.22mA
654.5mV   29.22mA    15.79mA    41.66mA
1.527V    39.09mA    19.05mA    59.31mA
2.345V    39.14mA    18.78mA    59.5mA
2.618V    38.71mA    5.636mA    59.27mA
2.782V    23.04mA    2.689mA    58.16mA
3.055V    4.158mA    1.352mA    10.28mA
3.545V    1.801mA    1.153mA    2.203mA
[Pullup]
-1.8V     3.998mA    3.315mA    4.26mA
-1.2V     11.17mA    6.515mA    16.05mA
-1.091V   19.96mA    9.525mA    37.2mA
-1.036V   30.02mA    12.16mA    66.24mA
-981.8mV  47.48mA    16.29mA    92.63mA
-927.3mV  64.64mA    22.8mA     97.4mA
-872.7mV  69.46mA    31.49mA    96.17mA
-763.6mV  64.03mA    39.31mA    86.78mA
54.55mV   -3.696mA   -2.123mA   -5.184mA
709.1mV   -31.49mA   -14.6mA    -47.82mA
2.127V    -39.64mA   -17mA      -62.9mA
3.545V    -36.43mA   -15.79mA   -56.35mA
[GND_clamp]
-1.8V     -794.1mA   -670.5mA   -980.8mA
-1.109V   -139.6mA   -162.5mA   -140mA
-1.073V   -112.7mA   -141.5mA   -105.3mA
-1.036V   -89.23mA   -122.4mA   -75.75mA
-1V       -69.83mA   -105.6mA   -53.36mA
-963.6mV  -54.49mA   -90.99mA   -38.21mA
-890.9mV  -31.19mA   -66.62mA   -21.14mA
-818.2mV  -14.71mA   -45.88mA   -13.31mA
-709.1mV  -3.87mA    -20.18mA   -5.973mA
-600mV    -903.1uA   -4.176mA   -1.354mA
-490.9mV  -116.3uA   -342.2uA   -105.5uA
1.764V    389.6pA    119.4nA    561.5pA
[Ramp]
dV/dt_f  0.7768223/0.2723781n   0.525039/0.7528542n  0.9052803/0.1448492n
dV/dt_r  0.8014638/0.202021n   0.4702814/0.5682539n  0.9373594/0.1020281n
R_load = 50
[Rising Waveform]
R_fixture = 50
V_fixture = 1.8
V_fixture_min = 1.62
V_fixture_max = 1.89
0s        536mV      762.7mV    425mV
56ps      536.6mV    762.7mV    734.4mV
112ps     535.8mV    762.7mV    1.66V
168ps     529.5mV    762.6mV    1.869V
288ps     612mV      762.7mV    1.888V
392ps     1.496V     763.5mV    1.889V
464ps     1.762V     763.9mV    1.89V
912ps     1.799V     762.7mV    1.89V
1.2ns     1.8V       1.547V     1.89V
1.656ns   1.8V       1.617V     1.89V
[Rising Waveform]
R_fixture = 50
V_fixture = 0
V_fixture_min = 0
V_fixture_max = 0
0s        241.6nV    156.2nV    521.6nV
64ps      646.1uV    2.79uV     74.71mV
160ps     1.606mV    3.123uV    1.013V
208ps     -5.713mV   152.6nV    1.311V
312ps     -31.99mV   -92.38uV   1.483V
576ps     953.2mV    867.4uV    1.521V
784ps     1.243V     291.9uV    1.524V
1.16ns    1.298V     13.35mV    1.524V
1.968ns   1.303V     653.1mV    1.524V
3.36ns    1.303V     757.4mV    1.524V
[Falling Waveform]
R_fixture = 50
V_fixture = 1.8
V_fixture_min = 1.62
V_fixture_max = 1.89
0s        1.8V       1.62V      1.89V
48ps      1.8V       1.62V      1.87V
136ps     1.798V     1.62V      1.158V
240ps     1.813V     1.62V      654.9mV
376ps     1.663V     1.62V      459.3mV
664ps     804.1mV    1.62V      427.7mV
880ps     584.1mV    1.623V     425.5mV
1.232ns   542mV      1.604V     425mV
2.272ns   536mV      856.6mV    425mV
3.584ns   536mV      766mV      425mV
[Falling Waveform]
R_fixture = 50
V_fixture = 0
V_fixture_min = 0
V_fixture_max = 0
0s        1.303V     760.8mV    1.524V
56ps      1.303V     760.8mV    1.392V
144ps     1.302V     760.8mV    264.1mV
208ps     1.317V     760.8mV    36.6mV
280ps     1.26V      760.8mV    12.44mV
408ps     320mV      760.8mV    4.369mV
488ps     56.43mV    760.8mV    2.607mV
928ps     2.589mV    816.8mV    104.2uV
1.32ns    374.7uV    50.22mV    7.096uV
2.104ns   15.48uV    3.301mV    513.6nV
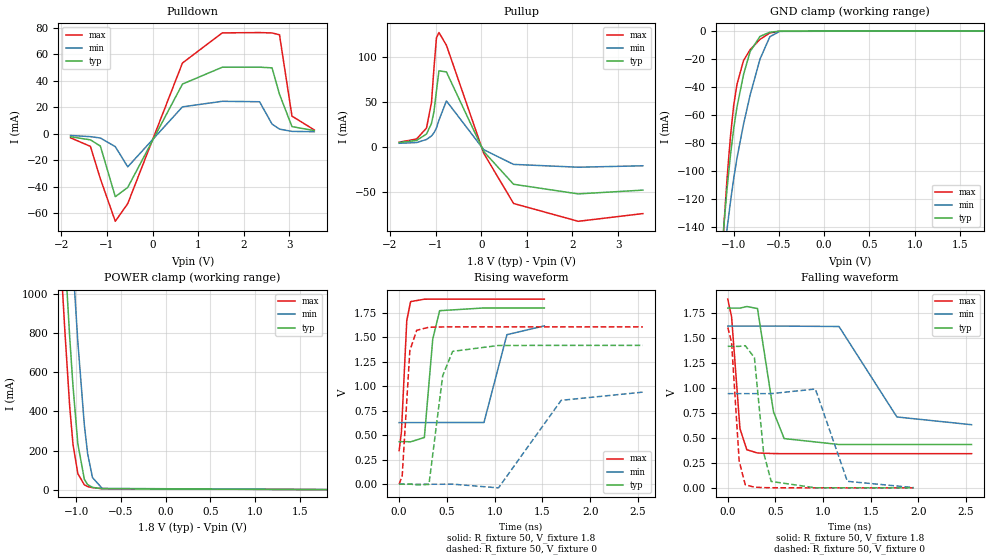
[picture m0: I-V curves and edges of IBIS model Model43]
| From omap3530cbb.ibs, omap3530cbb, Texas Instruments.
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| Model based on original model for BQOMAPPROGIOCSHYFBPB_7LM
|   Sub model MODE00_PU_ON_1P8
[model]   Model43
|[Input Load]   PU
|[Output Drive] DS00
|Voltage   1.8V
|Mode   I/O
Model_type   I/O
Polarity   Non-Inverting
Enable   Active-Low
Vinl =  0.63
Vinh =  1.17
Cref =  15.0000pF
Rref =  100.0000M
Vref =  0V
Vmeas =  0.9
C_comp   0.8864943p   0.7714798p   1.034566p
[Model Spec]
Vinl   0.63   0.567   0.6615
Vinh   1.17   1.053   1.2285
[Temperature Range]   25   125   -40
[Voltage Range]   1.8   1.62   1.89
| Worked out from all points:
|   slope of the pulldown table from 0 to 0.27 V, typ, clamps not added: 15 ohm
|   slope of the pullup table from 0 to 0.27 V, typ, clamps not added: 12.7 ohm
|   GND clamp passes 1 mA (typ) near -0.60 V on its own axis
|   POWER clamp passes 1 mA (typ) near -0.55 V on its own axis
|   rising waveform, R_fixture 50, V_fixture 1.8: 20-80 % time 67.3ps typ, 113ps min, 44.6ps max; typ from 0.435 V to 1.8 V
|   rising waveform, R_fixture 50, V_fixture 0: 20-80 % time 114ps typ, 355ps min, 58.4ps max; typ from 0.001 V to 1.42 V
|   falling waveform, R_fixture 50, V_fixture 1.8: 20-80 % time 131ps typ, 343ps min, 70.2ps max; typ from 1.8 V to 0.435 V
|   falling waveform, R_fixture 50, V_fixture 0: 20-80 % time 90.7ps typ, 152ps min, 64.1ps max; typ from 1.42 V to 0.001 V
[POWER_clamp]
-1.8V     7.429A     8.065A     7.064A
-1.182V   1.663A     2.35A      1.259A
-1.164V   1.508A     2.193A     1.106A
-1.127V   1.206A     1.883A     813.3mA
-1.073V   782.1mA    1.435A     426.4mA
-1.036V   530.7mA    1.15A      232.5mA
-981.8mV  234.7mA    756.4mA    81.82mA
-909.1mV  52.91mA    331.4mA    24.57mA
-872.7mV  25.71mA    185.5mA    15.52mA
-818.2mV  11.31mA    62.04mA    10.16mA
-709.1mV  4.634mA    6.205mA    4.543mA
1.8V      403.3pA    2.083nA    554.5pA
[Pulldown]
-1.8V     -2.297mA   -1.36mA    -3.12mA
-1.364V   -4.671mA   -2.227mA   -9.575mA
-1.145V   -9.38mA    -3.274mA   -34.14mA
-818.2mV  -47.59mA   -9.8mA     -66.19mA
-545.5mV  -40.61mA   -25.06mA   -52.83mA
654.5mV   37.49mA    20.27mA    53.42mA
1.527V    50.2mA     24.47mA    76.15mA
2.345V    50.26mA    24.12mA    76.39mA
2.618V    49.72mA    7.253mA    76.1mA
2.782V    29.73mA    3.458mA    74.71mA
3.055V    5.351mA    1.737mA    13.28mA
3.545V    2.313mA    1.481mA    2.83mA
[Pullup]
-1.8V     5.219mA    4.328mA    5.561mA
-1.418V   7.442mA    5.119mA    9.078mA
-1.2V     14.66mA    8.527mA    21.18mA
-1.091V   26.28mA    12.48mA    49.44mA
-1.036V   39.59mA    15.94mA    87.85mA
-981.8mV  62.55mA    21.35mA    121.3mA
-927.3mV  84.62mA    29.9mA     127mA
-763.6mV  83.4mA     51.27mA    113mA
54.55mV   -4.816mA   -2.769mA   -6.75mA
709.1mV   -41.09mA   -19.06mA   -62.37mA
2.127V    -51.75mA   -22.2mA    -82.12mA
3.545V    -47.57mA   -20.61mA   -73.57mA
[GND_clamp]
-1.8V     -794.1mA   -670.5mA   -980.8mA
-1.109V   -139.6mA   -162.6mA   -140.1mA
-1.073V   -112.8mA   -141.5mA   -105.3mA
-1.036V   -89.25mA   -122.4mA   -75.78mA
-1V       -69.85mA   -105.6mA   -53.39mA
-963.6mV  -54.51mA   -91mA      -38.25mA
-890.9mV  -31.23mA   -66.63mA   -21.22mA
-818.2mV  -14.77mA   -45.89mA   -13.43mA
-709.1mV  -3.956mA   -20.2mA    -6.107mA
-600mV    -995.8uA   -4.202mA   -1.492mA
-490.9mV  -212.7uA   -380.9uA   -249.1uA
1.764V    -5.644uA   14.27uA    -26.63uA
[Ramp]
dV/dt_f  0.8478999/0.1308941n  0.6111268/0.3535442n  0.9668412/72.74829p
dV/dt_r   0.883358/0.1141162n  0.5900634/0.3616776n   1.002765/59.10541p
R_load = 50
[Rising Waveform]
R_fixture = 50
V_fixture = 1.8
V_fixture_min = 1.62
V_fixture_max = 1.89
0s        434.5mV    629.8mV    343.2mV
24ps      434.8mV    629.8mV    534.2mV
80ps      434.9mV    629.8mV    1.672V
120ps     433.7mV    629.8mV    1.865V
264ps     477.9mV    629.8mV    1.889V
352ps     1.483V     630.2mV    1.89V
424ps     1.772V     630.6mV    1.89V
888ps     1.8V       630.9mV    1.89V
1.128ns   1.8V       1.527V     1.89V
1.52ns    1.8V       1.617V     1.89V
[Rising Waveform]
R_fixture = 50
V_fixture = 0
V_fixture_min = 0
V_fixture_max = 0
0s        1.095mV    716.6uV    1.279mV
32ps      1.432mV    718.8uV    86.17mV
112ps     2.9mV      719.7uV    1.364V
184ps     -6.472mV   716.5uV    1.572V
312ps     -1.031mV   633.1uV    1.603V
456ps     1.109V     802.2uV    1.606V
560ps     1.357V     1.475mV    1.607V
1.04ns    1.417V     -36.2mV    1.607V
1.696ns   1.418V     857.1mV    1.607V
2.552ns   1.418V     940.9mV    1.607V
[Falling Waveform]
R_fixture = 50
V_fixture = 1.8
V_fixture_min = 1.62
V_fixture_max = 1.89
0s        1.8V       1.62V      1.89V
40ps      1.8V       1.62V      1.715V
128ps     1.8V       1.62V      593.3mV
200ps     1.816V     1.62V      382.7mV
312ps     1.796V     1.62V      350.3mV
480ps     763mV      1.62V      344.2mV
592ps     494.4mV    1.62V      343.6mV
1.168ns   435mV      1.616V     343.2mV
1.776ns   434.6mV    710.6mV    343.2mV
2.56ns    434.5mV    633.2mV    343.2mV
[Falling Waveform]
R_fixture = 50
V_fixture = 0
V_fixture_min = 0
V_fixture_max = 0
0s        1.418V     944.2mV    1.607V
40ps      1.418V     944.2mV    1.458V
120ps     1.417V     944.2mV    267.4mV
184ps     1.424V     944.2mV    31.68mV
280ps     1.304V     944.2mV    8.239mV
376ps     355mV      944.2mV    3.713mV
456ps     65.27mV    944.2mV    2.296mV
920ps     1.928mV    990.2mV    1.311mV
1.256ns   1.2mV      66.44mV    1.283mV
1.952ns   1.104mV    4.033mV    1.279mV
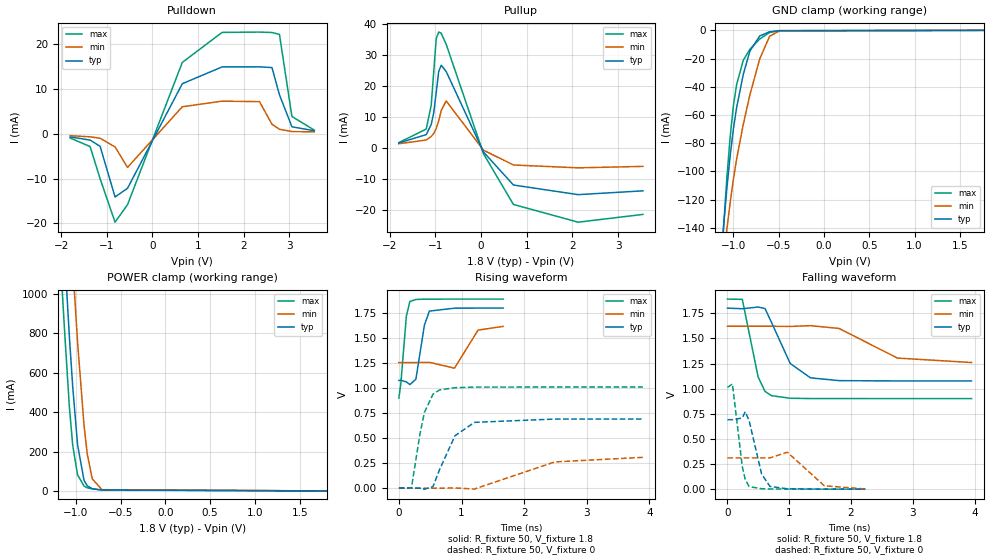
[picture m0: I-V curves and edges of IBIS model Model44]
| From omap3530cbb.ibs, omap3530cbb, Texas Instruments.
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| Model based on original model for BQOMAPPROGIOCSHYFBPB_7LM
|   Sub model MODE11_PU_ON_1P8
[model]   Model44
|[Input Load]   PU
|[Output Drive] DS11
|Voltage   1.8V
|Mode   I/O
Model_type   I/O
Polarity   Non-Inverting
Enable   Active-Low
Vinl =  0.63
Vinh =  1.17
Cref =  15.0000pF
Rref =  100.0000M
Vref =  0V
Vmeas =  0.9
C_comp   0.8864943p   0.7714798p   1.034566p
[Model Spec]
Vinl   0.63   0.567   0.6615
Vinh   1.17   1.053   1.2285
[Temperature Range]   25   125   -40
[Voltage Range]   1.8   1.62   1.89
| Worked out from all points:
|   slope of the pulldown table from 0 to 0.27 V, typ, clamps not added: 50.2 ohm
|   slope of the pullup table from 0 to 0.27 V, typ, clamps not added: 43.2 ohm
|   GND clamp passes 1 mA (typ) near -0.60 V on its own axis
|   POWER clamp passes 1 mA (typ) near -0.55 V on its own axis
|   rising waveform, R_fixture 50, V_fixture 1.8: 20-80 % time 107ps typ, 167ps min, 76.3ps max; typ from 1.08 V to 1.8 V
|   rising waveform, R_fixture 50, V_fixture 0: 20-80 % time 312ps typ, 718ps min, 176ps max; typ from 0.002 V to 0.692 V
|   falling waveform, R_fixture 50, V_fixture 1.8: 20-80 % time 339ps typ, 637ps min, 199ps max; typ from 1.8 V to 1.08 V
|   falling waveform, R_fixture 50, V_fixture 0: 20-80 % time 161ps typ, 304ps min, 110ps max; typ from 0.692 V to 0.002 V
[POWER_clamp]
-1.8V     7.429A     8.065A     7.064A
-1.182V   1.663A     2.35A      1.259A
-1.164V   1.508A     2.193A     1.106A
-1.127V   1.206A     1.883A     813.3mA
-1.073V   782.1mA    1.435A     426.4mA
-1.036V   530.7mA    1.15A      232.5mA
-981.8mV  234.7mA    756.4mA    81.82mA
-909.1mV  52.91mA    331.4mA    24.57mA
-872.7mV  25.71mA    185.5mA    15.52mA
-818.2mV  11.31mA    62.04mA    10.16mA
-709.1mV  4.634mA    6.205mA    4.543mA
1.8V      403.3pA    2.083nA    554.5pA
[Pulldown]
-1.8V     -685.7uA   -406.8uA   -929.8uA
-1.364V   -1.393mA   -666uA     -2.846mA
-1.145V   -2.793mA   -979uA     -10.06mA
-818.2mV  -14.12mA   -2.924mA   -19.76mA
-545.5mV  -12.18mA   -7.506mA   -15.84mA
654.5mV   11.22mA    6.067mA    15.99mA
1.527V    14.98mA    7.316mA    22.7mA
2.345V    15mA       7.209mA    22.77mA
2.618V    14.83mA    2.157mA    22.68mA
2.782V    8.739mA    1.031mA    22.24mA
3.055V    1.587mA    518.5uA    3.885mA
3.545V    690.3uA    442.8uA    842.1uA
[Pullup]
-1.8V     1.529mA    1.269mA    1.629mA
-1.2V     4.224mA    2.481mA    6.016mA
-1.091V   7.505mA    3.622mA    13.74mA
-1.036V   11.25mA    4.62mA     24.52mA
-981.8mV  17.83mA    6.179mA    35.2mA
-927.3mV  24.58mA    8.646mA    37.31mA
-872.7mV  26.61mA    11.97mA    36.93mA
-763.6mV  24.59mA    15.07mA    33.37mA
54.55mV   -1.419mA   -813.6uA   -1.993mA
709.1mV   -12.05mA   -5.587mA   -18.32mA
2.127V    -15.16mA   -6.505mA   -24.05mA
3.545V    -13.93mA   -6.04mA    -21.54mA
[GND_clamp]
-1.8V     -794.1mA   -670.5mA   -980.8mA
-1.109V   -139.6mA   -162.6mA   -140.1mA
-1.073V   -112.8mA   -141.5mA   -105.3mA
-1.036V   -89.25mA   -122.4mA   -75.78mA
-1V       -69.85mA   -105.6mA   -53.39mA
-963.6mV  -54.51mA   -91mA      -38.25mA
-890.9mV  -31.23mA   -66.63mA   -21.22mA
-818.2mV  -14.77mA   -45.89mA   -13.43mA
-709.1mV  -3.956mA   -20.2mA    -6.107mA
-600mV    -995.8uA   -4.202mA   -1.492mA
-490.9mV  -212.7uA   -380.9uA   -249.1uA
1.764V    -5.644uA   14.27uA    -26.63uA
[Ramp]
dV/dt_f  0.4404178/0.3400176n  0.2215649/0.6533786n  0.6022591/0.2002352n
dV/dt_r  0.4226645/0.312342n   0.1924714/0.7440211n  0.6162526/0.1763874n
R_load = 50
[Rising Waveform]
R_fixture = 50
V_fixture = 1.8
V_fixture_min = 1.62
V_fixture_max = 1.89
0s        1.077V     1.256V     901.7mV
32ps      1.079V     1.256V     1.049V
120ps     1.063V     1.256V     1.721V
176ps     1.036V     1.256V     1.866V
272ps     1.09V      1.256V     1.886V
408ps     1.63V      1.258V     1.889V
488ps     1.77V      1.258V     1.889V
888ps     1.799V     1.2V       1.89V
1.264ns   1.8V       1.58V      1.89V
1.664ns   1.8V       1.617V     1.89V
[Rising Waveform]
R_fixture = 50
V_fixture = 0
V_fixture_min = 0
V_fixture_max = 0
0s        2.434mV    1.374mV    3.067mV
200ps     5.088mV    1.379mV    2.846mV
336ps     1.51mV     1.368mV    539.8mV
408ps     -7.972mV   1.261mV    757.8mV
544ps     16.38mV    1.308mV    939.3mV
648ps     184.3mV    1.969mV    982.8mV
896ps     525.5mV    3.676mV    1.005V
1.208ns   659.2mV    -6.27mV    1.011V
2.488ns   692mV      264mV      1.012V
3.896ns   692.1mV    309.7mV    1.012V
[Falling Waveform]
R_fixture = 50
V_fixture = 1.8
V_fixture_min = 1.62
V_fixture_max = 1.89
0s        1.8V       1.62V      1.89V
240ps     1.794V     1.62V      1.887V
496ps     1.811V     1.62V      1.117V
608ps     1.796V     1.62V      973.2mV
712ps     1.659V     1.62V      931.1mV
1.016ns   1.25V      1.618V     905mV
1.344ns   1.108V     1.626V     902.2mV
1.808ns   1.08V      1.598V     901.9mV
2.752ns   1.077V     1.304V     901.8mV
3.952ns   1.077V     1.26V      901.8mV
[Falling Waveform]
R_fixture = 50
V_fixture = 0
V_fixture_min = 0
V_fixture_max = 0
0s        692.1mV    313mV      1.012V
80ps      692.2mV    313mV      1.048V
240ps     709.5mV    313mV      224.7mV
288ps     771.4mV    313mV      97.71mV
352ps     679.4mV    313mV      27.36mV
552ps     153.9mV    313.1mV    7.113mV
688ps     29.48mV    313mV      4.706mV
968ps     6.367mV    369.7mV    3.324mV
1.568ns   2.685mV    35.99mV    3.074mV
2.232ns   2.457mV    4.683mV    3.068mV
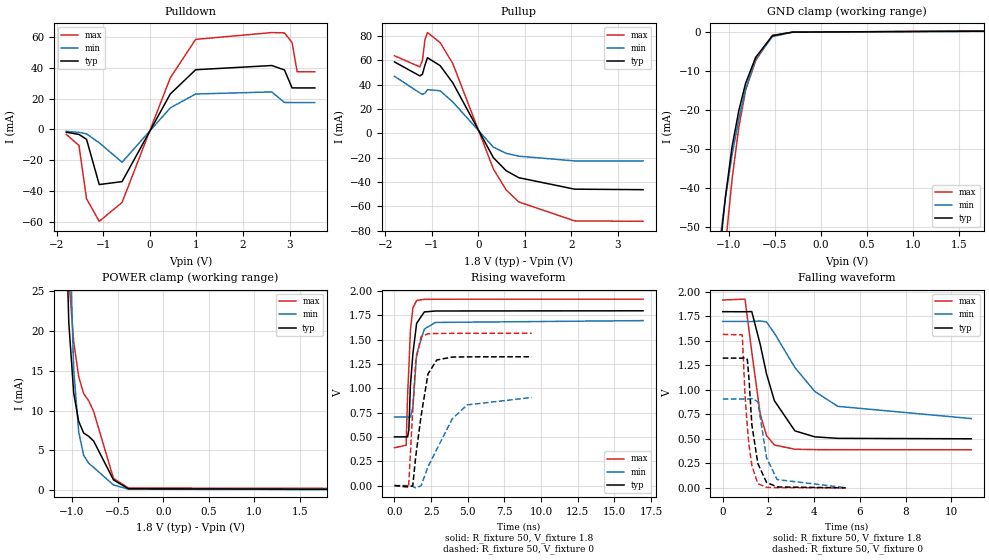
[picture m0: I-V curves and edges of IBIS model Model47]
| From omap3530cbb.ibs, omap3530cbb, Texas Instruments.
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| Model based on original model for CCPV2_7LM
|   Sub model CCPV2_7LM_SP_PD
[model]   Model47
|[Input Load]   PD
|[Output Drive]
|Voltage   1.8V
|Mode   I/O
Model_type   I/O
Polarity   Non-Inverting
Enable   Active-Low
Vinl =  0.63
Vinh =  1.17
Cref =  15.0000pF
Rref =  100.0000M
Vref =  0V
Vmeas =  0.9
C_comp   5.837306p   5.73806p   5.865695p
[Model Spec]
Vinl   0.63   0.595   0.672
Vinh   1.17   1.105   1.248
[Temperature Range]   25   125   -40
[Voltage Range]   1.8   1.7   1.92
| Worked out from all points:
|   slope of the pulldown table from 0 to 0.27 V, typ, clamps not added: 17.9 ohm
|   slope of the pullup table from 0 to 0.27 V, typ, clamps not added: 15.8 ohm
|   GND clamp passes 1 mA (typ) near -0.52 V on its own axis
|   POWER clamp passes 1 mA (typ) near -0.52 V on its own axis
|   rising waveform, R_fixture 50, V_fixture 1.8: 20-80 % time 322ps typ, 441ps min, 235ps max; typ from 0.501 V to 1.8 V
|   rising waveform, R_fixture 50, V_fixture 0: 20-80 % time 730ps typ, 1.88ns min, 371ps max; typ from 0 V to 1.32 V
|   falling waveform, R_fixture 50, V_fixture 1.8: 20-80 % time 927ps typ, 1.98ns min, 522ps max; typ from 1.8 V to 0.501 V
|   falling waveform, R_fixture 50, V_fixture 0: 20-80 % time 358ps typ, 464ps min, 290ps max; typ from 1.32 V to 0 V
[POWER_clamp]
-1.8V     2.373A     2.073A     2.673A
-1.055V   29.29mA    52.56mA    32mA
-1.036V   21.11mA    35.66mA    26.7mA
-1.018V   18.14mA    28.82mA    24.02mA
-981.8mV  12.19mA    15.14mA    18.64mA
-927.3mV  8.661mA    7.341mA    14.28mA
-872.7mV  7.197mA    4.409mA    12.15mA
-818.2mV  6.781mA    3.395mA    11.26mA
-763.6mV  6.196mA    2.874mA    9.913mA
-545.5mV  1.307mA    668.9uA    1.492mA
-381.8mV  191.7uA    136.8uA    285.1uA
1.8V      134.1uA    86.36uA    239.5uA
[Pulldown]
-1.8V     -1.759mA   -1.185mA   -3.17mA
-1.527V   -3.214mA   -1.876mA   -10.31mA
-1.364V   -6.349mA   -2.806mA   -44.88mA
-1.091V   -35.7mA    -8.628mA   -59.51mA
-600mV    -33.78mA   -21.21mA   -47.31mA
436.4mV   23mA       13.98mA    33.47mA
981.8mV   38.72mA    23mA       58.39mA
2.618V    41.46mA    24.35mA    62.82mA
2.891V    38.61mA    17.5mA     62.59mA
3.055V    26.96mA    17.47mA    56.44mA
3.164V    26.94mA    17.45mA    37.42mA
3.545V    26.92mA    17.44mA    37.37mA
[Pullup]
-1.8V     58.82mA    46.97mA    63.88mA
-1.255V   47.3mA     33.32mA    54.75mA
-1.2V     48.59mA    32.13mA    59.92mA
-1.145V   56.22mA    33.1mA     77.09mA
-1.091V   62.26mA    36mA       82.99mA
-818.2mV  55.76mA    35.07mA    74.72mA
-545.5mV  41.53mA    25.83mA    57.35mA
327.3mV   -20.08mA   -11.4mA    -29.4mA
600mV     -30.72mA   -16.43mA   -46.55mA
872.7mV   -36.53mA   -18.79mA   -56.47mA
2.073V    -45.96mA   -22.7mA    -72.08mA
3.545V    -46.38mA   -22.69mA   -72.42mA
[GND_clamp]
-1.8V     -272.3mA   -226.4mA   -345.1mA
-1.145V   -69.43mA   -63.58mA   -89.25mA
-1.109V   -59.86mA   -56.2mA    -77.02mA
-1.073V   -50.83mA   -49.2mA    -65.58mA
-1.036V   -42.34mA   -42.58mA   -54.91mA
-963.6mV  -29.42mA   -31.54mA   -37.73mA
-890.9mV  -20.23mA   -22.4mA    -24.52mA
-818.2mV  -13.3mA    -14.83mA   -15.1mA
-709.1mV  -6.603mA   -6.973mA   -7.447mA
-527.3mV  -1.042mA   -1.293mA   -892.3uA
-309.1mV  -104.1uA   -80.93uA   -150.4uA
1.764V    133.6uA    87.03uA    236.1uA
[Ramp]
dV/dt_f  0.7843685/0.9300527n  0.5995975/1.993453n   0.9251847/0.5244278n
dV/dt_r  0.8154604/0.7408622n  0.5591701/1.908982n   0.9650723/0.3770168n
R_load = 50
[Rising Waveform]
R_fixture = 50
V_fixture = 1.8
V_fixture_min = 1.7
V_fixture_max = 1.92
0s        501.1mV    705.8mV    389.2mV
795ps     501.1mV    705.9mV    414.8mV
895ps     500.7mV    705.8mV    934.7mV
980ps     574.2mV    705.3mV    1.207V
1.085ns   1.025V     704.8mV    1.593V
1.255ns   1.356V     809.5mV    1.827V
1.51ns    1.669V     1.35V      1.904V
2.035ns   1.786V     1.61V      1.916V
2.785ns   1.796V     1.678V     1.917V
16.96ns   1.798V     1.697V     1.918V
[Rising Waveform]
R_fixture = 50
V_fixture = 0
V_fixture_min = 0
V_fixture_max = 0
0s        508.6nV    512nV      796.2nV
960ps     -8.69mV    101.3uV    -19.41mV
1.245ns   -3.957mV   -9.222mV   773.9mV
1.45ns    300.8mV    -23.56mV   1.285V
1.815ns   716.1mV    -2.652mV   1.533V
2.285ns   1.148V     192.7mV    1.562V
2.885ns   1.292V     372.8mV    1.565V
3.935ns   1.322V     684.9mV    1.566V
4.955ns   1.324V     829.8mV    1.566V
9.36ns    1.325V     906.2mV    1.567V
[Falling Waveform]
R_fixture = 50
V_fixture = 1.8
V_fixture_min = 1.7
V_fixture_max = 1.92
0s        1.799V     1.699V     1.918V
975ps     1.798V     1.699V     1.927V
1.27ns    1.8V       1.698V     1.388V
1.64ns    1.464V     1.704V     753.7mV
1.915ns   1.164V     1.694V     534mV
2.26ns    890mV      1.579V     437.6mV
3.155ns   582.2mV    1.229V     394.7mV
4.025ns   521.1mV    984.4mV    390.4mV
5.03ns    505.7mV    832.5mV    389.7mV
10.87ns   501.2mV    707.5mV    389.3mV
[Falling Waveform]
R_fixture = 50
V_fixture = 0
V_fixture_min = 0
V_fixture_max = 0
0s        1.325V     907.9mV    1.567V
855ps     1.325V     908mV      1.562V
975ps     1.33V      907.7mV    945.3mV
1.075ns   1.312V     907.5mV    629.4mV
1.15ns    1.108V     907.6mV    436.6mV
1.275ns   641.9mV    912.3mV    228.1mV
1.535ns   249.4mV    879.9mV    43.1mV
1.915ns   55.93mV    307.6mV    5.565mV
2.38ns    9.579mV    84.98mV    1.971mV
5.385ns   316.8uV    1.703mV    247.1uV
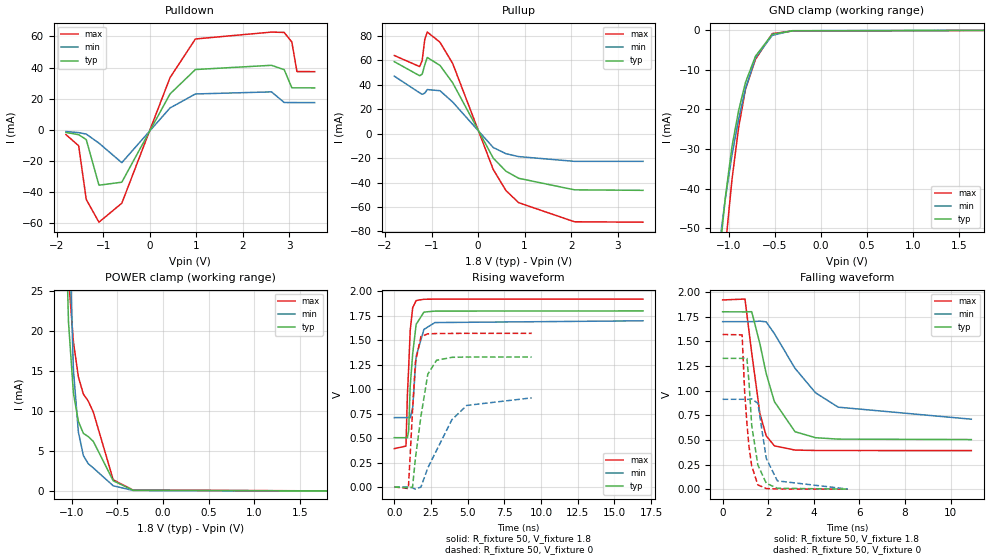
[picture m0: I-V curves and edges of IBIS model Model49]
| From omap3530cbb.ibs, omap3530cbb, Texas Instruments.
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| Model based on original model for CCPV2_7LM
|   Sub model CCPV2_7LM_SP_PU
[model]   Model49
|[Input Load]   PU
|[Output Drive]
|Voltage   1.8V
|Mode   I/O
Model_type   I/O
Polarity   Non-Inverting
Enable   Active-Low
Vinl =  0.63
Vinh =  1.17
Cref =  15.0000pF
Rref =  100.0000M
Vref =  0V
Vmeas =  0.9
C_comp   5.837306p   5.73806p   5.865695p
[Model Spec]
Vinl   0.63   0.595   0.672
Vinh   1.17   1.105   1.248
[Temperature Range]   25   125   -40
[Voltage Range]   1.8   1.7   1.92
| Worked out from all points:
|   slope of the pulldown table from 0 to 0.27 V, typ, clamps not added: 17.9 ohm
|   slope of the pullup table from 0 to 0.27 V, typ, clamps not added: 15.8 ohm
|   GND clamp passes 1 mA (typ) near -0.53 V on its own axis
|   POWER clamp passes 1 mA (typ) near -0.52 V on its own axis
|   rising waveform, R_fixture 50, V_fixture 1.8: 20-80 % time 320ps typ, 434ps min, 233ps max; typ from 0.505 V to 1.8 V
|   rising waveform, R_fixture 50, V_fixture 0: 20-80 % time 727ps typ, 1.88ns min, 369ps max; typ from 0.001 V to 1.33 V
|   falling waveform, R_fixture 50, V_fixture 1.8: 20-80 % time 930ps typ, 1.98ns min, 525ps max; typ from 1.8 V to 0.505 V
|   falling waveform, R_fixture 50, V_fixture 0: 20-80 % time 363ps typ, 471ps min, 295ps max; typ from 1.33 V to 0.002 V
[POWER_clamp]
-1.8V     2.373A     2.073A     2.673A
-1.055V   29.33mA    52.58mA    32mA
-1.036V   21.15mA    35.68mA    26.71mA
-1.018V   18.17mA    28.84mA    24.01mA
-981.8mV  12.22mA    15.16mA    18.63mA
-927.3mV  8.682mA    7.356mA    14.25mA
-872.7mV  7.209mA    4.419mA    12.12mA
-818.2mV  6.785mA    3.399mA    11.22mA
-763.6mV  6.193mA    2.873mA    9.859mA
-545.5mV  1.271mA    644.9uA    1.391mA
-327.3mV  81.73uA    57.46uA    110.1uA
1.8V      3.334uA    1.489uA    7.395uA
[Pulldown]
-1.8V     -1.758mA   -1.185mA   -3.17mA
-1.527V   -3.214mA   -1.876mA   -10.31mA
-1.364V   -6.349mA   -2.806mA   -44.88mA
-1.091V   -35.7mA    -8.628mA   -59.51mA
-600mV    -33.78mA   -21.21mA   -47.31mA
436.4mV   23mA       13.98mA    33.48mA
981.8mV   38.72mA    23mA       58.39mA
2.618V    41.45mA    24.35mA    62.82mA
2.891V    38.61mA    17.5mA     62.59mA
3.055V    26.96mA    17.47mA    56.43mA
3.164V    26.94mA    17.45mA    37.42mA
3.545V    26.92mA    17.44mA    37.37mA
[Pullup]
-1.8V     58.82mA    46.97mA    63.88mA
-1.255V   47.3mA     33.32mA    54.75mA
-1.2V     48.6mA     32.13mA    59.92mA
-1.145V   56.22mA    33.1mA     77.09mA
-1.091V   62.26mA    36mA       82.99mA
-818.2mV  55.76mA    35.07mA    74.72mA
-545.5mV  41.53mA    25.83mA    57.35mA
327.3mV   -20.08mA   -11.4mA    -29.39mA
600mV     -30.72mA   -16.43mA   -46.55mA
872.7mV   -36.53mA   -18.79mA   -56.47mA
2.073V    -45.97mA   -22.7mA    -72.08mA
3.545V    -46.38mA   -22.69mA   -72.42mA
[GND_clamp]
-1.8V     -272.3mA   -226.4mA   -345.1mA
-1.145V   -69.39mA   -63.56mA   -89.21mA
-1.109V   -59.82mA   -56.18mA   -76.99mA
-1.073V   -50.79mA   -49.18mA   -65.54mA
-1.036V   -42.29mA   -42.56mA   -54.86mA
-963.6mV  -29.35mA   -31.51mA   -37.66mA
-890.9mV  -20.15mA   -22.36mA   -24.41mA
-818.2mV  -13.21mA   -14.78mA   -14.97mA
-709.1mV  -6.517mA   -6.916mA   -7.325mA
-527.3mV  -988.8uA   -1.253mA   -816.3uA
-309.1mV  -113.9uA   -78.9uA    -169.2uA
1.764V    -2.91uA    8.74uA     -29.34uA
[Ramp]
dV/dt_f  0.7838102/0.9334095n  0.5985059/1.996356n   0.9258623/0.5273244n
dV/dt_r  0.8157371/0.7377899n  0.5609374/1.904864n   0.9648584/0.3751914n
R_load = 50
[Rising Waveform]
R_fixture = 50
V_fixture = 1.8
V_fixture_min = 1.7
V_fixture_max = 1.92
0s        504.5mV    709.4mV    392.7mV
795ps     504.5mV    709.6mV    418.7mV
895ps     504.1mV    709.5mV    944.6mV
980ps     578.6mV    708.9mV    1.218V
1.085ns   1.033V     708.4mV    1.601V
1.255ns   1.363V     814.1mV    1.832V
1.49ns    1.662V     1.337V     1.905V
2.02ns    1.787V     1.61V      1.918V
2.765ns   1.797V     1.68V      1.919V
16.95ns   1.799V     1.698V     1.92V
[Rising Waveform]
R_fixture = 50
V_fixture = 0
V_fixture_min = 0
V_fixture_max = 0
0s        1.303mV    999uV      1.531mV
960ps     -7.302mV   1.099mV    -14.93mV
1.245ns   -172.7uV   -8.138mV   782.8mV
1.44ns    293.5mV    -21.26mV   1.275V
1.815ns   723.1mV    -210.1uV   1.537V
2.285ns   1.153V     195.7mV    1.565V
2.88ns    1.295V     375.3mV    1.568V
3.93ns    1.325V     689.1mV    1.569V
4.945ns   1.328V     834.1mV    1.57V
9.37ns    1.328V     911.1mV    1.57V
[Falling Waveform]
R_fixture = 50
V_fixture = 1.8
V_fixture_min = 1.7
V_fixture_max = 1.92
0s        1.8V       1.7V       1.92V
980ps     1.799V     1.7V       1.929V
1.275ns   1.801V     1.7V       1.386V
1.635ns   1.476V     1.705V     768.2mV
1.91ns    1.175V     1.698V     543.4mV
2.27ns    889.9mV    1.579V     440.9mV
3.175ns   584.2mV    1.227V     398mV
4.075ns   523.4mV    978.8mV    393.8mV
5.07ns    509mV      832.9mV    393.1mV
10.91ns   504.6mV    711.1mV    392.7mV
[Falling Waveform]
R_fixture = 50
V_fixture = 0
V_fixture_min = 0
V_fixture_max = 0
0s        1.328V     912.8mV    1.57V
855ps     1.328V     912.9mV    1.566V
965ps     1.332V     912.6mV    993.8mV
1.065ns   1.327V     912.4mV    669.7mV
1.155ns   1.093V     912.5mV    437mV
1.275ns   649.4mV    917.1mV    238.4mV
1.545ns   247.7mV    872.7mV    44.85mV
1.915ns   61.02mV    313.1mV    7.542mV
2.4ns     11.13mV    85.58mV    3.526mV
5.495ns   1.607mV    2.704mV    1.768mV
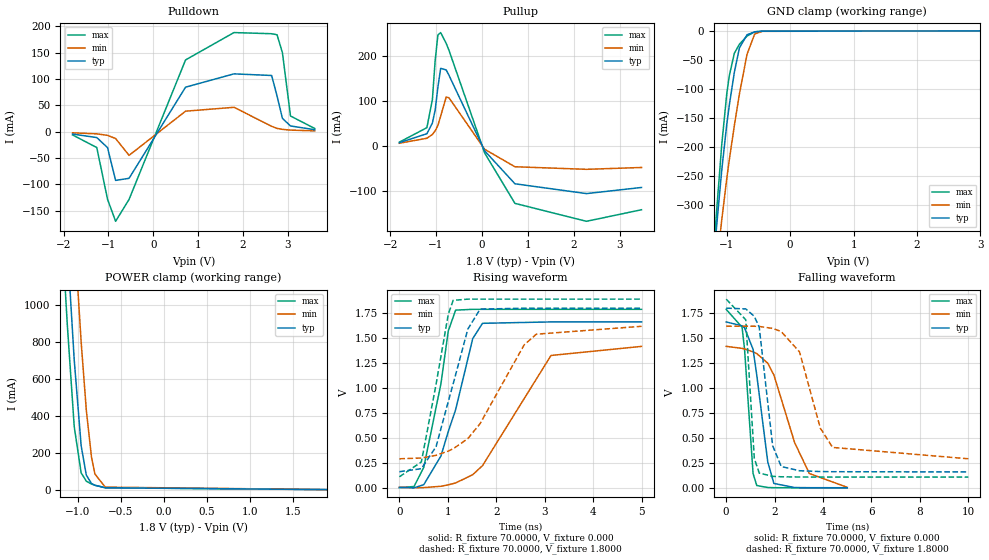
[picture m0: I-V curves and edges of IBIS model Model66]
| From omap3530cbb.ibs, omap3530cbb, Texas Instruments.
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| Model based on original model for BQ0245S_7LM
|   Sub model BQ0245S_7LM_NOM
[model]   Model66
|[Input Load]
|[Output Drive]
|Voltage   1.8000V
|Mode   I/O
Model_type   I/O
Polarity   Non-Inverting
Enable   Active-Low
Vinl =   0.6615V
Vinh =   1.0530V
Vmeas =   0.9000V
Cref =  15.0000pF
Rref =  70.0000
Vref =  0.000V
C_comp   27.0438pF   15.4231pF   39.2246pF
[Temperature Range]   25.0000   0.1250k   -40.0000
[Voltage Range]   1.8000V   1.6200V   1.8900V
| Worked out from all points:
|   slope of the pulldown table from 0 to 0.27 V, typ, clamps not added: 7.04 ohm
|   slope of the pullup table from 0 to 0.27 V, typ, clamps not added: 6.3 ohm
|   GND clamp passes 1 mA (typ) near -0.50 V on its own axis
|   POWER clamp passes 1 mA (typ) near -0.43 V on its own axis
|   rising waveform, R_fixture 70.0000, V_fixture 0.000: 20-80 % time 554ps typ, 991ps min, 387ps max; typ from 0.003 V to 1.66 V
|   rising waveform, R_fixture 70.0000, V_fixture 1.8000: 20-80 % time 532ps typ, 960ps min, 375ps max; typ from 0.161 V to 1.8 V
|   falling waveform, R_fixture 70.0000, V_fixture 0.000: 20-80 % time 520ps typ, 1.16ns min, 294ps max; typ from 1.66 V to 0.003 V
|   falling waveform, R_fixture 70.0000, V_fixture 1.8000: 20-80 % time 410ps typ, 906ps min, 240ps max; typ from 1.8 V to 0.161 V
[Pulldown]
-1.8V     -4.511mA   -2.201mA   -6.192mA
-1.26V    -11.21mA   -4.169mA   -30.18mA
-1.02V    -30.36mA   -6.981mA   -128.5mA
-840mV    -92.69mA   -13.08mA   -170.4mA
-540mV    -88.67mA   -45.07mA   -128.8mA
720mV     84.59mA    38.95mA    136.4mA
1.8V      109.9mA    46.31mA    188.4mA
2.64V     106.8mA    10.19mA    186.2mA
2.76V     67.85mA    6.207mA    184.2mA
2.88V     25.33mA    4.367mA    150.2mA
3.06V     10.85mA    2.983mA    29.78mA
3.6V      3.724mA    1.501mA    6.092mA
[Pullup]
-1.8V     7.702mA    6.395mA    8.832mA
-1.2V     27.56mA    17.46mA    41mA
-1.08V    51.16mA    25.93mA    103.4mA
-1.02V    79.92mA    33.59mA    189.6mA
-960mV    130.8mA    46.03mA    247.2mA
-900mV    172.9mA    66.38mA    252.5mA
-780mV    169.5mA    109mA      228.7mA
-720mV    157.8mA    107.7mA    213.5mA
60mV      -10.64mA   -7.064mA   -15.37mA
720mV     -83.76mA   -45.9mA    -127.3mA
2.28V     -105.6mA   -51.62mA   -167.2mA
3.48V     -91.97mA   -47.52mA   -141.5mA
[GND_clamp]
-1.8V     -1.222A    -1.152A    -1.363A
-1.2V     -387.2mA   -450.4mA   -371mA
-1.16V    -336.3mA   -407.6mA   -310.2mA
-1.08V    -241mA     -326.5mA   -197.1mA
-1V       -161.1mA   -254.5mA   -108.6mA
-960mV    -128mA     -222.2mA   -77.39mA
-880mV    -71.16mA   -162.8mA   -38.56mA
-800mV    -29.23mA   -108.5mA   -22.98mA
-680mV    -6.794mA   -40.29mA   -9.022mA
-560mV    -1.73mA    -5.516mA   -1.725mA
-440mV    -712.5uA   -866.2uA   -705.6uA
3.6V      0A         0A         0A
[POWER_clamp]
-1.8V     7.644A     8.363A     7.23A
-1.2V     2.004A     2.755A     1.56A
-1.18V    1.829A     2.579A     1.386A
-1.14V    1.487A     2.23A      1.05A
-1.12V    1.32A      2.059A     889.4mA
-1.04V    700.8mA    1.398A     340.5mA
-960mV    238.1mA    800.5mA    90.89mA
-900mV    78.42mA    430.4mA    45.59mA
-840mV    33.07mA    175.9mA    30.03mA
-800mV    23.35mA    84.15mA    23.7mA
-680mV    10.28mA    13.34mA    9.595mA
1.89V     0A         0A         0A
[Ramp]
dV/dt_r   0.9946/0.5475n   0.8470/1.0408n   1.0703/0.3876n
dV/dt_f   0.9818/0.4110n   0.7944/0.9130n   1.0671/0.2359n
R_load = 70.0000
[Rising Waveform]
R_fixture = 70.0000
V_fixture = 0.000
V_fixture_min = 0.000
V_fixture_max = 0.000
0s        2.503mV    4.25mV     1.743mV
303ps     -1.068mV   771.3uV    12.42mV
505.1ps   31.58mV    1.42mV     206.1mV
858.6ps   318.2mV    14.98mV    1.042V
1.01ns    562.8mV    29.04mV    1.57V
1.162ns   781.8mV    47.93mV    1.778V
1.515ns   1.493V     130.8mV    1.786V
1.717ns   1.646V     221.5mV    1.786V
3.131ns   1.66V      1.324V     1.786V
5ns       1.66V      1.415V     1.786V
[Rising Waveform]
R_fixture = 70.0000
V_fixture = 1.8000
V_fixture_min = 1.6200
V_fixture_max = 1.8900
0s        160.7mV    289.8mV    109.4mV
454.5ps   190.9mV    297.6mV    258.2mV
757.6ps   410.7mV    324.6mV    1.036V
1.01ns    863.5mV    367.3mV    1.737V
1.111ns   1.04V      390.2mV    1.876V
1.414ns   1.588V     491.8mV    1.888V
1.667ns   1.788V     642.3mV    1.888V
2.576ns   1.797V     1.43V      1.888V
2.828ns   1.797V     1.537V     1.888V
5ns       1.797V     1.616V     1.888V
[Falling Waveform]
R_fixture = 70.0000
V_fixture = 0.000
V_fixture_min = 0.000
V_fixture_max = 0.000
0s        1.66V      1.416V     1.786V
656.6ps   1.621V     1.396V     1.607V
757.6ps   1.602V     1.39V      1.39V
1.111ns   1.386V     1.361V     145mV
1.263ns   1.129V     1.344V     25.17mV
1.717ns   261.6mV    1.248V     5.487mV
1.97ns    46.01mV    1.13V      3.741mV
2.828ns   5.023mV    453.4mV    2.256mV
3.434ns   3.704mV    145.5mV    2.098mV
5ns       2.987mV    7.371mV    1.99mV
[Falling Waveform]
R_fixture = 70.0000
V_fixture = 1.8000
V_fixture_min = 1.6200
V_fixture_max = 1.8900
0s        1.798V     1.617V     1.888V
808.1ps   1.79V      1.618V     1.682V
1.162ns   1.716V     1.617V     295.5mV
1.364ns   1.608V     1.615V     149.9mV
1.919ns   423.6mV    1.595V     116.9mV
2.273ns   215.3mV    1.564V     112.7mV
3.03ns    173mV      1.36V      110.4mV
3.889ns   165mV      598.1mV    109.9mV
4.394ns   163.4mV    406mV      109.8mV
10ns      161.1mV    292.6mV    109.7mV
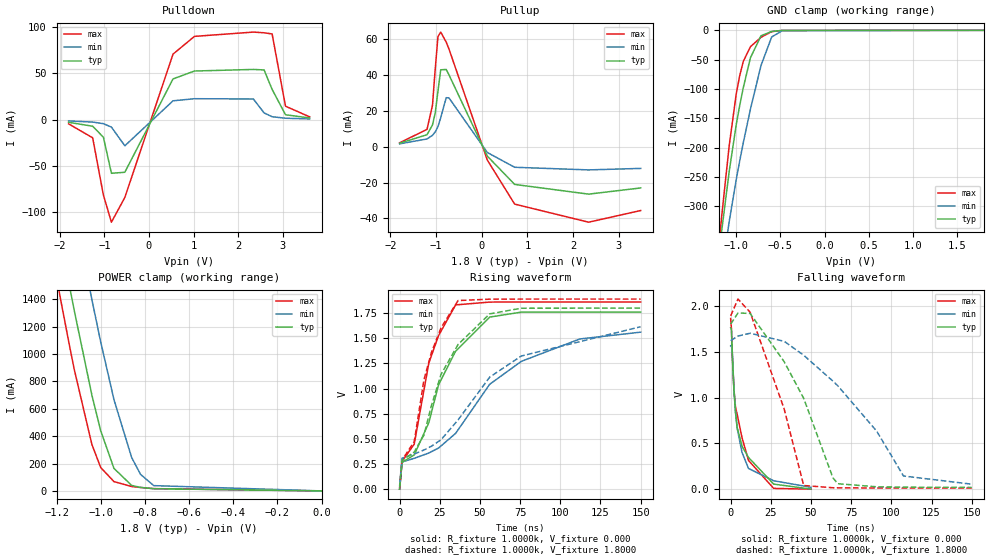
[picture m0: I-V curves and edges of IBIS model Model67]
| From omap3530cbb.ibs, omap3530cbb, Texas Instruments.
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| Model based on original model for BQ0245S_7LM
|   Sub model BQ0245S_7LM_I2C_2
[model]   Model67
|[Input Load]
|[Output Drive] HIGHC
|Voltage   1.8000V
|Mode   I/O
Model_type   I/O
Polarity   Non-Inverting
Enable   Active-Low
Vinl =   0.6615V
Vinh =   1.0530V
Vmeas =   0.9000V
Cref =  400pF
Rref =  70.0000
Vref =  1.800V
C_comp   27.0438pF   15.4231pF   39.2246pF
[Temperature Range]   25.0000   0.1250k   -40.0000
[Voltage Range]   1.8000V   1.6200V   1.8900V
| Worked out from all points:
|   slope of the pulldown table from 0 to 0.27 V, typ, clamps not added: 11 ohm
|   slope of the pullup table from 0 to 0.27 V, typ, clamps not added: 25 ohm
|   GND clamp passes 1 mA (typ) near -0.56 V on its own axis
|   POWER clamp passes 1 mA (typ) near -0.50 V on its own axis
|   rising waveform, R_fixture 1.0000k, V_fixture 0.000: 20-80 % time 26.7ns typ, 63.8ns min, 16ns max; typ from 0 V to 1.76 V
|   rising waveform, R_fixture 1.0000k, V_fixture 1.8000: 20-80 % time 27.3ns typ, 64.7ns min, 16.3ns max; typ from 0.018 V to 1.8 V
|   falling waveform, R_fixture 1.0000k, V_fixture 0.000: 20-80 % time 9.75ns typ, 6.74ns min, 8.84ns max; typ from 1.76 V to 0.001 V
|   falling waveform, R_fixture 1.0000k, V_fixture 1.8000: 20-80 % time 28ns typ, 43.8ns min, 19.5ns max; typ from 1.8 V to 0.019 V
[Pulldown]
-1.8V     -2.87mA    -1.375mA   -4.529mA
-1.26V    -7.104mA   -2.598mA   -19.64mA
-1.02V    -19.01mA   -4.336mA   -81.54mA
-840mV    -58.01mA   -8.07mA    -110.9mA
-540mV    -56.9mA    -28.27mA   -84.17mA
540mV     44.08mA    20.39mA    70.89mA
1.02V     52.6mA     22.66mA    90.08mA
2.34V     54.32mA    22.39mA    94.72mA
2.58V     53.78mA    7.279mA    93.97mA
2.76V     32.75mA    3.192mA    92.7mA
3.06V     5.313mA    1.539mA    14.56mA
3.6V      1.834mA    776uA      3.052mA
[Pullup]
-1.8V     1.906mA    1.589mA    2.175mA
-1.2V     6.671mA    4.3mA      9.635mA
-1.08V    12.15mA    6.353mA    23.09mA
-1.02V    18.75mA    8.199mA    43.3mA
-960mV    31mA       11.19mA    61.33mA
-900mV    42.83mA    16.12mA    63.84mA
-780mV    43.01mA    27.29mA    58.28mA
-720mV    40.08mA    27.21mA    54.48mA
120mV     -5.231mA   -3.221mA   -7.396mA
720mV     -21.02mA   -11.47mA   -31.99mA
2.34V     -26.43mA   -12.93mA   -42.06mA
3.48V     -22.99mA   -12.1mA    -35.57mA
[GND_clamp]
-1.8V     -1.221A    -1.151A    -1.363A
-1.2V     -386.5mA   -449.7mA   -370.2mA
-1.16V    -335.5mA   -406.8mA   -309.4mA
-1.08V    -240.2mA   -325.8mA   -196.3mA
-1V       -160.3mA   -253.8mA   -107.7mA
-960mV    -127.1mA   -221.5mA   -76.33mA
-920mV    -97.28mA   -191.1mA   -52.71mA
-840mV    -46.78mA   -134.3mA   -27.94mA
-720mV    -9.253mA   -59.82mA   -11.79mA
-600mV    -1.888mA   -11.35mA   -2.27mA
-480mV    -137.6uA   -650.3uA   -84.11uA
1.8V      510.5nA    3.196uA    487.6nA
[POWER_clamp]
-1.8V     7.644A     8.363A     7.23A
-1.2V     2.004A     2.755A     1.56A
-1.18V    1.829A     2.578A     1.386A
-1.14V    1.486A     2.23A      1.05A
-1.12V    1.32A      2.059A     889mA
-1.04V    700.2mA    1.398A     339.6mA
-1V       439.3mA    1.088A     170.8mA
-940mV    164.6mA    666.7mA    68.12mA
-860mV    40.26mA    244.2mA    32.15mA
-820mV    25.73mA    121.5mA    25.04mA
-760mV    16.31mA    38.76mA    16.75mA
0V        510.5nA    462.5nA    537.3nA
[Ramp]
dV/dt_r   1.0568/26.4372n   0.9382/63.9463n   1.1166/15.9693n
dV/dt_f   1.0691/27.6993n   0.9470/45.0396n   1.1268/19.3181n
R_load = 1.0000k
[Rising Waveform]
R_fixture = 1.0000k
V_fixture = 0.000
V_fixture_min = 0.000
V_fixture_max = 0.000
0s        4.659uV    8.55uV     3.644uV
1.515ns   265.9mV    270.7mV    275.4mV
9.091ns   341.1mV    306.5mV    447.7mV
18.18ns   661.2mV    359.4mV    1.254V
24.24ns   1.038V     409.1mV    1.527V
34.85ns   1.372V     554.8mV    1.832V
56.06ns   1.711V     1.043V     1.86V
75.76ns   1.76V      1.271V     1.861V
112.1ns   1.761V     1.493V     1.861V
150ns     1.761V     1.561V     1.861V
[Rising Waveform]
R_fixture = 1.0000k
V_fixture = 1.8000
V_fixture_min = 1.6200
V_fixture_max = 1.8900
0s        17.75mV    32.71mV    11.97mV
1.515ns   286.3mV    307.8mV    289.2mV
9.091ns   369.1mV    350mV      472.9mV
15.15ns   538mV      389.2mV    1.088V
19.7ns    825.1mV    426mV      1.355V
25.76ns   1.141V     491mV      1.604V
36.36ns   1.438V     688.2mV    1.875V
56.06ns   1.743V     1.114V     1.889V
75.76ns   1.799V     1.324V     1.89V
150ns     1.8V       1.615V     1.89V
[Falling Waveform]
R_fixture = 1.0000k
V_fixture = 0.000
V_fixture_min = 0.000
V_fixture_max = 0.000
0s        1.761V     1.564V     1.861V
505.1ps   1.736V     1.559V     1.743V
1.01ns    1.474V     1.505V     1.461V
2.02ns    1.084V     1.104V     1.092V
3.03ns    836.9mV    834.9mV    892.6mV
4.04ns    675.1mV    666.2mV    817.9mV
7.071ns   468.2mV    400.3mV    561.6mV
11.11ns   345.9mV    225.8mV    313.2mV
26.77ns   55.51mV    92.17mV    8.679mV
50ns      958.3uV    20.55mV    199.4uV
[Falling Waveform]
R_fixture = 1.0000k
V_fixture = 1.8000
V_fixture_min = 1.6200
V_fixture_max = 1.8900
0s        1.8V       1.62V      1.89V
4.546ns   1.922V     1.671V     2.074V
12.12ns   1.917V     1.701V     1.93V
33.33ns   1.39V      1.613V     873.1mV
45.45ns   990.9mV    1.461V     40.09mV
63.64ns   124mV      1.179V     15.62mV
66.67ns   59.64mV    1.128V     14.89mV
90.91ns   26mV       632.1mV    12.62mV
107.6ns   22.08mV    143.8mV    12.27mV
150ns     18.97mV    54.56mV    12.02mV
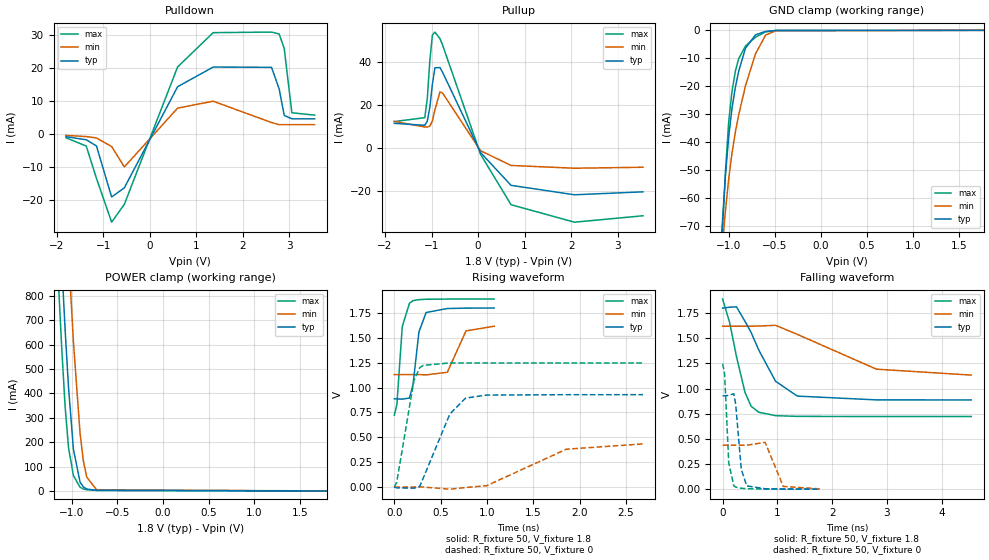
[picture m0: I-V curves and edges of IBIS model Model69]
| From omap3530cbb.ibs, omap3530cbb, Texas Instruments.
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| Model based on original model for BQ0226CS_7LM
|   Sub model 0226CS_PD_PU_OFF_1P8
[model]   Model69
|[Input Load]   PI
|[Output Drive]
|Voltage   1.8V
|Mode   I/O
Model_type   I/O
Polarity   Non-Inverting
Enable   Active-Low
Vinl =  0.63
Vinh =  1.17
Cref =  15.0000pF
Rref =  100.0000M
Vref =  0V
Vmeas =  0.9
C_comp   0.742316p   0.619633p   0.9008309p
[Model Spec]
Vinl   0.63   0.567   0.6615
Vinh   1.17   1.053   1.2285
[Temperature Range]   25   125   -40
[Voltage Range]   1.8   1.62   1.89
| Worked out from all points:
|   slope of the pulldown table from 0 to 0.27 V, typ, clamps not added: 37.2 ohm
|   slope of the pullup table from 0 to 0.27 V, typ, clamps not added: 30.1 ohm
|   GND clamp passes 1 mA (typ) near -0.67 V on its own axis
|   POWER clamp passes 1 mA (typ) near -0.64 V on its own axis
|   rising waveform, R_fixture 50, V_fixture 1.8: 20-80 % time 71.3ps typ, 113ps min, 54.6ps max; typ from 0.887 V to 1.8 V
|   rising waveform, R_fixture 50, V_fixture 0: 20-80 % time 255ps typ, 610ps min, 137ps max; typ from 0 V to 0.929 V
|   falling waveform, R_fixture 50, V_fixture 1.8: 20-80 % time 508ps typ, 1.11ns min, 284ps max; typ from 1.8 V to 0.887 V
|   falling waveform, R_fixture 50, V_fixture 0: 20-80 % time 89.6ps typ, 149ps min, 64.2ps max; typ from 0.929 V to 0 V
[POWER_clamp]
-1.8V     6.299A     6.506A     6.196A
-1.164V   1.344A     1.893A     994.1mA
-1.127V   1.063A     1.63A      711.7mA
-1.109V   925.8mA    1.498A     579.2mA
-1.073V   661.5mA    1.236A     346.8mA
-1.036V   426.8mA    976.8mA    179mA
-981.8mV  170.8mA    611.1mA    62.59mA
-909.1mV  36.17mA    236.5mA    15.31mA
-872.7mV  16.4mA     123mA      7.737mA
-836.4mV  7.815mA    57.2mA     5.017mA
-727.3mV  2.215mA    4.318mA    2.163mA
1.8V      5.377nA    2.929nA    8.928nA
[Pulldown]
-1.8V     -923.4uA   -546.6uA   -1.251mA
-1.364V   -1.871mA   -894.2uA   -3.779mA
-1.145V   -3.734mA   -1.313mA   -13.56mA
-818.2mV  -19.23mA   -3.924mA   -26.88mA
-545.5mV  -16.45mA   -10.11mA   -21.46mA
600mV     14.23mA    7.738mA    20.24mA
1.364V    20.2mA     9.834mA    30.64mA
2.618V    20.12mA    3.366mA    30.81mA
2.782V    13.57mA    2.716mA    30.25mA
2.891V    5.527mA    2.714mA    25.85mA
3.055V    4.494mA    2.712mA    6.326mA
3.545V    4.488mA    2.709mA    5.61mA
[Pullup]
-1.8V     11.56mA    12.44mA    12.38mA
-1.145V   10.65mA    9.865mA    14.2mA
-1.091V   12.57mA    9.798mA    22.99mA
-1.036V   19.01mA    10.29mA    40.58mA
-981.8mV  29.64mA    12.69mA    52.6mA
-927.3mV  37.42mA    17.78mA    54mA
-818.2mV  37.48mA    26.16mA    50.92mA
-763.6mV  35.38mA    25.7mA     48.06mA
54.55mV   -2.036mA   -1.184mA   -2.863mA
709.1mV   -17.28mA   -8.025mA   -26.29mA
2.073V    -21.67mA   -9.32mA    -34.42mA
3.545V    -20.3mA    -8.865mA   -31.43mA
[GND_clamp]
-1.8V     -645.6mA   -500mA     -849.8mA
-1.073V   -71.04mA   -78.87mA   -76.37mA
-1.036V   -52.49mA   -64.91mA   -51.16mA
-1V       -38.08mA   -53.21mA   -32.92mA
-963.6mV  -27.84mA   -43.85mA   -21.66mA
-927.3mV  -20.38mA   -36.36mA   -14.61mA
-890.9mV  -14.57mA   -30.15mA   -10.12mA
-818.2mV  -6.416mA   -19.89mA   -5.619mA
-709.1mV  -1.607mA   -8.383mA   -2.459mA
-600mV    -378.7uA   -1.711mA   -563.3uA
-490.9mV  -49.84uA   -141.5uA   -43.56uA
1.764V    4.448nA    18.02nA    4.794nA
[Ramp]
dV/dt_f  0.5594463/0.5180791n  0.3003819/1.158992n   0.7162101/0.2904692n
dV/dt_r  0.5794385/0.2629095n  0.2755355/0.6394739n  0.7771597/0.1412873n
R_load = 50
[Rising Waveform]
R_fixture = 50
V_fixture = 1.8
V_fixture_min = 1.62
V_fixture_max = 1.89
0s        887.2mV    1.131V     722.4mV
28ps      887.3mV    1.131V     830.4mV
86ps      883.9mV    1.131V     1.614V
164ps     895.6mV    1.131V     1.848V
202ps     1.029V     1.131V     1.874V
266ps     1.56V      1.131V     1.884V
344ps     1.755V     1.128V     1.888V
572ps     1.795V     1.154V     1.89V
774ps     1.799V     1.57V      1.89V
1.078ns   1.8V       1.617V     1.89V
[Rising Waveform]
R_fixture = 50
V_fixture = 0
V_fixture_min = 0
V_fixture_max = 0
0s        161.4nV    66.38nV    364.7nV
26ps      -7.491mV   228.7nV    47.91mV
212ps     -10.99mV   236.5uV    1.071V
274ps     7.279mV    256uV      1.2V
314ps     93.71mV    161uV      1.224V
600ps     735.7mV    -20.75mV   1.248V
770ps     894.5mV    -4.393mV   1.248V
998ps     925.1mV    14.48mV    1.248V
1.856ns   928.8mV    380.7mV    1.248V
2.684ns   928.9mV    434.2mV    1.248V
[Falling Waveform]
R_fixture = 50
V_fixture = 1.8
V_fixture_min = 1.62
V_fixture_max = 1.89
0s        1.8V       1.62V      1.89V
128ps     1.809V     1.62V      1.657V
252ps     1.813V     1.62V      1.321V
408ps     1.669V     1.62V      963.1mV
520ps     1.558V     1.62V      824.2mV
660ps     1.383V     1.622V     764.8mV
966ps     1.073V     1.629V     730.9mV
1.364ns   925.3mV    1.539V     723.6mV
2.808ns   887.6mV    1.193V     722.4mV
4.54ns    887.3mV    1.134V     722.4mV
[Falling Waveform]
R_fixture = 50
V_fixture = 0
V_fixture_min = 0
V_fixture_max = 0
0s        929mV      437.5mV    1.248V
36ps      928.4mV    437.6mV    1.148V
112ps     932.5mV    437.4mV    258.9mV
204ps     948.8mV    437.1mV    33.33mV
238ps     846.2mV    437.1mV    20.73mV
340ps     199.2mV    437mV      9.082mV
440ps     32.6mV     437.1mV    4.369mV
776ps     4.255mV    465.3mV    1.046mV
1.106ns   1.692mV    27.51mV    206.5uV
1.774ns   320.5uV    3.254mV    12.42uV
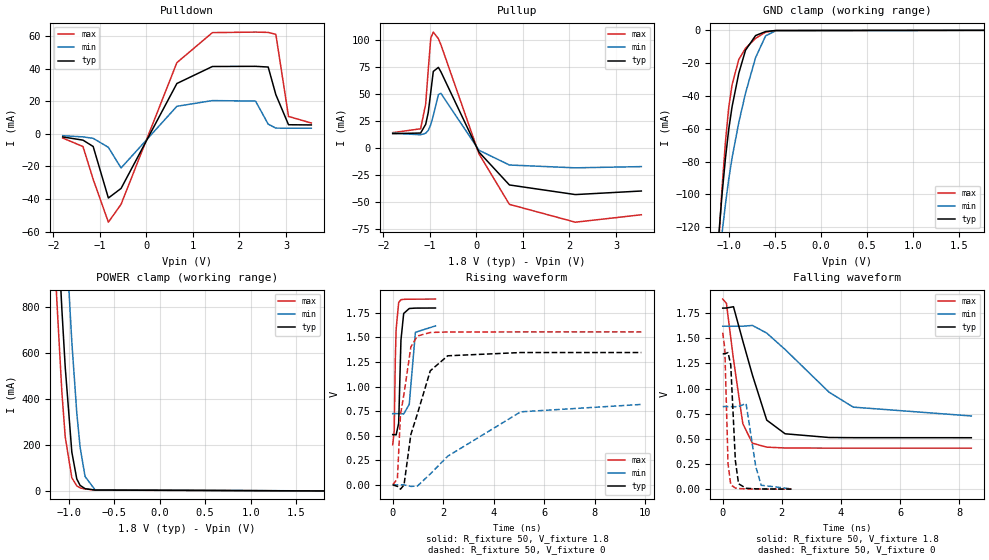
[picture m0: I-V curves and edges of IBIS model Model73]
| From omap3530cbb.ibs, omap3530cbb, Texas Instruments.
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| Model based on original model for SDI2_7LM
|   Sub model SDI2_7LM_PD_PU_OFF
[model]   Model73
|[Input Load]   PI
|[Output Drive]
|Voltage   1.8V
|Mode   I/O
Model_type   I/O
Polarity   Non-Inverting
Enable   Active-Low
Vinl =  0.63
Vinh =  1.17
Cref =  15.0000pF
Rref =  100.0000M
Vref =  0V
Vmeas =  0.9
C_comp   0.898823p   0.7724811p   1.056895p
[Model Spec]
Vinl   0.63   0.567   0.6615
Vinh   1.17   1.053   1.2285
[Temperature Range]   25   125   -40
[Voltage Range]   1.8   1.62   1.89
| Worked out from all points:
|   slope of the pulldown table from 0 to 0.27 V, typ, clamps not added: 18.2 ohm
|   slope of the pullup table from 0 to 0.27 V, typ, clamps not added: 15.1 ohm
|   GND clamp passes 1 mA (typ) near -0.62 V on its own axis
|   POWER clamp passes 1 mA (typ) near -0.57 V on its own axis
|   rising waveform, R_fixture 50, V_fixture 1.8: 20-80 % time 83ps typ, 144ps min, 66.8ps max; typ from 0.511 V to 1.8 V
|   rising waveform, R_fixture 50, V_fixture 0: 20-80 % time 778ps typ, 2.5ns min, 382ps max; typ from 0 V to 1.35 V
|   falling waveform, R_fixture 50, V_fixture 1.8: 20-80 % time 758ps typ, 1.98ns min, 423ps max; typ from 1.8 V to 0.511 V
|   falling waveform, R_fixture 50, V_fixture 0: 20-80 % time 127ps typ, 250ps min, 81.7ps max; typ from 1.35 V to 0.001 V
[POWER_clamp]
-1.8V     7.03A      7.477A     6.772A
-1.182V   1.672A     2.34A      1.267A
-1.164V   1.518A     2.189A     1.114A
-1.127V   1.216A     1.889A     820.4mA
-1.073V   791.2mA    1.448A     431.2mA
-1.036V   538.2mA    1.164A     234.5mA
-963.6mV  168.9mA    647.7mA    57.19mA
-909.1mV  51.95mA    338.6mA    22.02mA
-872.7mV  24.13mA    189.8mA    13.26mA
-818.2mV  9.807mA    62.59mA    8.409mA
-709.1mV  3.786mA    4.97mA     3.667mA
1.8V      5.761nA    3.974nA    9.478nA
[Pulldown]
-1.8V     -1.896mA   -1.14mA    -2.549mA
-1.364V   -3.858mA   -1.868mA   -7.811mA
-1.145V   -7.758mA   -2.749mA   -27.9mA
-818.2mV  -39.37mA   -8.281mA   -54.21mA
-545.5mV  -33.5mA    -20.95mA   -43.25mA
654.5mV   30.89mA    16.9mA     43.69mA
1.418V    41.32mA    20.41mA    62.11mA
2.345V    41.43mA    20.12mA    62.44mA
2.618V    40.99mA    5.968mA    62.24mA
2.782V    24.07mA    3.525mA    61.09mA
3.055V    5.586mA    3.449mA    10.68mA
3.545V    5.467mA    3.446mA    6.63mA
[Pullup]
-1.8V     13mA       13.47mA    13.94mA
-1.2V     13.58mA    11.97mA    17.52mA
-1.091V   21.69mA    13.4mA     40.44mA
-1.036V   32.56mA    16.02mA    72.05mA
-981.8mV  51.54mA    21.35mA    101.5mA
-927.3mV  70.65mA    29.72mA    107.1mA
-818.2mV  74.4mA     49.19mA    101mA
-763.6mV  70.3mA     50.34mA    95.36mA
54.55mV   -4.056mA   -2.362mA   -5.695mA
709.1mV   -34.52mA   -16.04mA   -52.48mA
2.127V    -43.43mA   -18.65mA   -69.01mA
3.545V    -40.12mA   -17.52mA   -62.13mA
[GND_clamp]
-1.8V     -750.7mA   -623.4mA   -941.3mA
-1.109V   -125.7mA   -143.6mA   -129.8mA
-1.073V   -100.4mA   -123.9mA   -96.47mA
-1.036V   -78.31mA   -106.3mA   -68.22mA
-1V       -60.36mA   -90.82mA   -47.09mA
-963.6mV  -46.51mA   -77.66mA   -33.13mA
-890.9mV  -26.15mA   -56.23mA   -17.77mA
-818.2mV  -12.16mA   -38.38mA   -10.96mA
-709.1mV  -3.184mA   -16.64mA   -4.887mA
-600mV    -744.5uA   -3.377mA   -1.108mA
-490.9mV  -97.56uA   -277.8uA   -89.75uA
1.764V    4.801nA    31.67nA    5.321nA
[Ramp]
dV/dt_f  0.7837888/0.7661799n  0.5431564/2.013951n   0.906104/0.4284031n
dV/dt_r   0.834429/0.7789978n  0.5086089/2.531345n   0.9671437/0.3828019n
R_load = 50
[Rising Waveform]
R_fixture = 50
V_fixture = 1.8
V_fixture_min = 1.62
V_fixture_max = 1.89
0s        511.5mV    724.7mV    407.9mV
60ps      511.3mV    724.7mV    549.7mV
102ps     510.1mV    724.8mV    1.263V
136ps     508.6mV    724.9mV    1.584V
236ps     626.9mV    724.9mV    1.855V
326ps     1.472V     724.1mV    1.884V
434ps     1.743V     721.3mV    1.887V
654ps     1.794V     818.7mV    1.889V
898ps     1.798V     1.552V     1.889V
1.692ns   1.799V     1.617V     1.89V
[Rising Waveform]
R_fixture = 50
V_fixture = 0
V_fixture_min = 0
V_fixture_max = 0
0s        196.5nV    87.64nV    427nV
186ps     -15.34mV   13.59uV    62.4mV
308ps     -43.78mV   178.5uV    714.6mV
448ps     -287.6uV   -16.85uV   926.2mV
718ps     512.2mV    -15.74mV   1.403V
976ps     721.7mV    -12.07mV   1.514V
1.486ns   1.16V      110.7mV    1.55V
2.176ns   1.313V     291.3mV    1.555V
5.064ns   1.346V     742.9mV    1.556V
9.838ns   1.346V     818.1mV    1.556V
[Falling Waveform]
R_fixture = 50
V_fixture = 1.8
V_fixture_min = 1.62
V_fixture_max = 1.89
0s        1.8V       1.62V      1.89V
126ps     1.801V     1.62V      1.847V
364ps     1.814V     1.62V      1.291V
680ps     1.473V     1.62V      651mV
1.004ns   1.135V     1.628V     457mV
1.488ns   686.7mV    1.552V     417.9mV
2.108ns   550.7mV    1.389V     409.6mV
3.594ns   513.8mV    964.5mV    407.9mV
4.412ns   512mV      815.6mV    407.9mV
8.404ns   511.5mV    727.9mV    407.9mV
[Falling Waveform]
R_fixture = 50
V_fixture = 0
V_fixture_min = 0
V_fixture_max = 0
0s        1.346V     821.4mV    1.556V
72ps      1.346V     821.5mV    1.394V
180ps     1.358V     820.9mV    252.6mV
272ps     1.236V     820.5mV    43.52mV
428ps     283.3mV    820.2mV    10.88mV
536ps     53.62mV    821.7mV    6.742mV
790ps     8.82mV     851.3mV    2.159mV
1.118ns   3.276mV    223.4mV    1.156mV
1.3ns     2.119mV    38.79mV    772.9uV
2.322ns   699.5uV    3.248mV    85.28uV
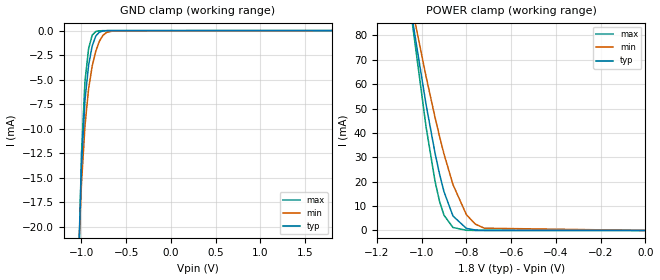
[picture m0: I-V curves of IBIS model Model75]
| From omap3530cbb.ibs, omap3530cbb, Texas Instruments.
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| Model based on original model for IQ0073S_7LM
|   Sub model IQ0073S_7LM
[model]   Model75
|[Input Load]
|[Output Drive]
|Voltage   1.8V
|Mode   INPUT
Model_type   Input
Polarity   Non-Inverting
Vinl =   0.6300V
Vinh =   1.1700V
C_comp   0.4476pF   0.5711pF   0.3401pF
[Temperature Range]   25.0000   0.1250k   -40.0000
[Pullup Reference]   1.8000V   1.6200V   1.8900V
[Pulldown Reference]   0.000V   0.000V   0.000V
[POWER Clamp Reference]   1.8000V   1.6200V   1.8900V
[GND Clamp Reference]   0.000V   0.000V   0.000V
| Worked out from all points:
|   GND clamp passes 1 mA (typ) near -0.86 V on its own axis
|   POWER clamp passes 1 mA (typ) near -0.80 V on its own axis
[GND_clamp]
-1.8V     -531.8mA   -376.4mA   -721.5mA
-1.04V    -25.69mA   -24.54mA   -28.36mA
-1V       -13.86mA   -15.68mA   -12.69mA
-960mV    -7.063mA   -9.661mA   -5.127mA
-920mV    -3.528mA   -5.934mA   -1.846mA
-880mV    -1.583mA   -3.628mA   -473.2uA
-840mV    -561.5uA   -2.111mA   -95.23uA
-800mV    -160.7uA   -1.099mA   -23.68uA
-760mV    -45.25uA   -490.2uA   -8.069uA
-720mV    -14.56uA   -191.5uA   -2.511uA
-640mV    -1.525uA   -26.38uA   -83.48nA
1.8V      795pA      1.097nA    765.9pA
[POWER_clamp]
-1.8V     607.2mA    493mA      733.8mA
-1.06V    97.91mA    99.72mA    99.01mA
-1.04V    85.77mA    90.25mA    83.94mA
-980mV    51.56mA    63.05mA    42.35mA
-940mV    31.68mA    46.34mA    20.13mA
-920mV    23.14mA    38.58mA    11.94mA
-900mV    15.87mA    31.34mA    6.234mA
-860mV    5.945mA    18.83mA    1.232mA
-800mV    847uA      6.468mA    76.31uA
-760mV    199.9uA    2.589mA    11.16uA
-720mV    45.12uA    934.5uA    1.618uA
0V        795pA      714.1pA    839.8pA
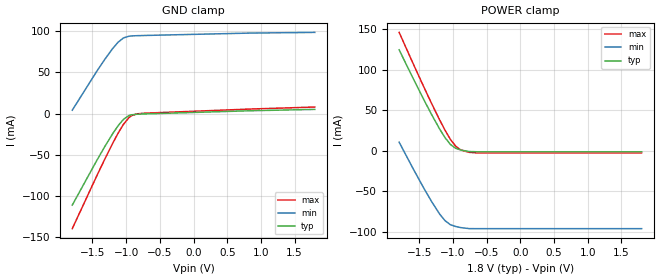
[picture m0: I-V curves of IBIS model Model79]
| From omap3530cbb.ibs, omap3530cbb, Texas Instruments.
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| Model based on original model for BQ0073VDDUS
|   Sub model XTAL_BYPASS
[model]   Model79
|[Input Load]
|[Output Drive]
|Voltage   1.8V
|Mode   INPUT
Model_type   Input
Vinl =   0.3V
Vinh =   1.5V
C_comp   2.2pF 1.97pF 2.39pF
[Temperature Range]   27.00   125   -40
[Voltage Range]   1.8V   1.69V   1.92V
[GND clamp]
-1.8V     -111.1mA   4.142mA    -139.7mA
-1.44V    -57.47mA   50.9mA     -76.23mA
-1.32V    -40.42mA   65.58mA    -55.73mA
-1.2V     -24.36mA   79.07mA    -36.05mA
-1.12V    -14.75mA   86.67mA    -23.82mA
-1.04V    -6.962mA   91.89mA    -13mA
-960mV    -2.435mA   93.99mA    -4.967mA
-920mV    -1.466mA   94.33mA    -2.51mA
-840mV    -756.5uA   94.63mA    -268.7uA
-720mV    -376.7uA   94.89mA    540.3uA
840mV     3.471mA    97.79mA    5.544mA
1.8V      5.112mA    98.62mA    7.977mA
[POWER_clamp]
-1.8V     124.3mA    10.34mA    145.8mA
-1.6V     90.27mA    -21.19mA   108.7mA
-1.44V    63.85mA    -45.46mA   79.62mA
-1.32V    44.73mA    -62.65mA   58.39mA
-1.2V     26.76mA    -78.15mA   38.01mA
-1.12V    16.1mA     -86.37mA   25.3mA
-1.04V    7.647mA    -91.42mA   13.97mA
-960mV    2.77mA     -93.71mA   5.311mA
-880mV    576.8uA    -95.08mA   625.3uA
-760mV    -1.176mA   -96.25mA   -2.14mA
-640mV    -1.472mA   -96.32mA   -2.91mA
1.8V      -1.474mA   -96.32mA   -2.924mA
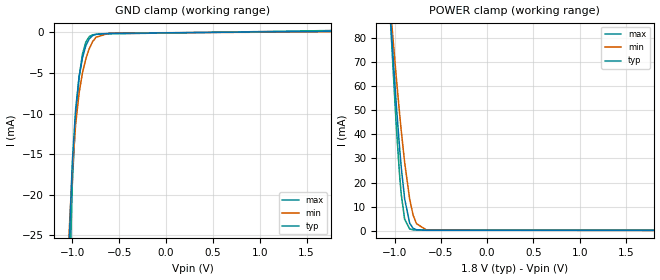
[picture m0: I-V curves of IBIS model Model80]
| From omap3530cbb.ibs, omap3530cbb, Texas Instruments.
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| Model based on original model for IQ0101CS_7LM
|   Sub model IQ0101CS_7LM_PD_ON_1P8
[model]   Model80
|[Input Load]   PD
|[Output Drive]
|Voltage   1.8V
|Mode   INPUT
Model_type   Input
Polarity   Non-Inverting
Vinl =  0.63
Vinh =  1.17
C_comp   0.4935895p   0.3850681p   0.6261927p
[Model Spec]
Vinl   0.63   0.567   0.6615
Vinh   1.17   1.053   1.2285
[Temperature Range]   25   125   -40
[Voltage Range]   1.8   1.62   1.89
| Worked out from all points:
|   GND clamp passes 1 mA (typ) near -0.83 V on its own axis
|   POWER clamp passes 1 mA (typ) near -0.80 V on its own axis
[POWER_clamp]
-1.8V     607.9mA    493.5mA    734.7mA
-1.055V   94.76mA    97.29mA    95.12mA
-1.036V   83.78mA    88.71mA    81.52mA
-981.8mV  52.7mA     63.98mA    43.76mA
-945.5mV  34.37mA    48.66mA    23.06mA
-927.3mV  26.29mA    41.47mA    14.94mA
-890.9mV  13.21mA    28.35mA    4.722mA
-836.4mV  3.075mA    13.06mA    676.1uA
-800mV    988.6uA    6.54mA     316.9uA
-763.6mV  371.7uA    2.911mA    251.6uA
-654.5mV  138.2uA    217.2uA    231.9uA
1.8V      125.3uA    51.97uA    219uA
[GND_clamp]
-1.8V     -542.2mA   -381.9mA   -758.2mA
-1.036V   -27.03mA   -25.19mA   -34.09mA
-1V       -16.09mA   -17.04mA   -18.77mA
-963.6mV  -9.394mA   -11.3mA    -10.26mA
-927.3mV  -5.505mA   -7.488mA   -5.505mA
-890.9mV  -3.123mA   -4.978mA   -2.678mA
-854.5mV  -1.634mA   -3.245mA   -1.185mA
-818.2mV  -800.4uA   -1.997mA   -529.7uA
-781.8mV  -408.7uA   -1.135mA   -311uA
-745.5mV  -243uA     -605.2uA   -252.1uA
-600mV    -131.7uA   -90.3uA    -193uA
1.764V    125uA      52.5uA     217.2uA
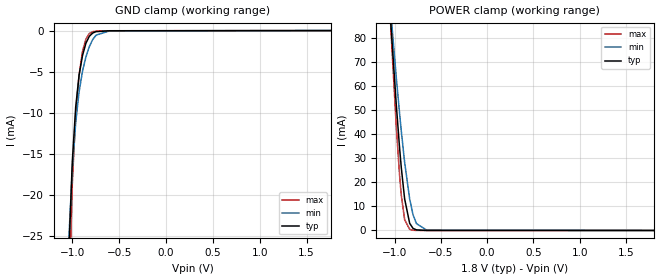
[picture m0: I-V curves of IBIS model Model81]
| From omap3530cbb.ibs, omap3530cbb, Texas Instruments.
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| Model based on original model for IQ0101CS_7LM
|   Sub model 0101CS_PD_PU_OFF_1P8
[model]   Model81
|[Input Load]   PI
|[Output Drive]
|Voltage   1.8V
|Mode   INPUT
Model_type   Input
Polarity   Non-Inverting
Vinl =  0.63
Vinh =  1.17
C_comp   0.4935895p   0.3850681p   0.6261927p
[Model Spec]
Vinl   0.63   0.567   0.6615
Vinh   1.17   1.053   1.2285
[Temperature Range]   25   125   -40
[Voltage Range]   1.8   1.62   1.89
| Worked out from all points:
|   GND clamp passes 1 mA (typ) near -0.83 V on its own axis
|   POWER clamp passes 1 mA (typ) near -0.80 V on its own axis
[POWER_clamp]
-1.8V     607.9mA    493.5mA    734.7mA
-1.055V   94.73mA    97.28mA    94.99mA
-1.036V   83.74mA    88.7mA     81.38mA
-981.8mV  52.64mA    63.97mA    43.58mA
-945.5mV  34.3mA     48.65mA    22.86mA
-927.3mV  26.21mA    41.46mA    14.74mA
-890.9mV  13.11mA    28.34mA    4.507mA
-836.4mV  2.958mA    13.04mA    455.1uA
-800mV    866.3uA    6.516mA    95.16uA
-763.6mV  246.9uA    2.881mA    29.25uA
-654.5mV  11.31uA    169uA      7.621uA
1.8V      5.364nA    2.422nA    8.89nA
[GND_clamp]
-1.8V     -542.2mA   -381.9mA   -758.2mA
-1.036V   -26.98mA   -25.17mA   -34.04mA
-1V       -16.04mA   -17.02mA   -18.71mA
-963.6mV  -9.334mA   -11.27mA   -10.18mA
-927.3mV  -5.437mA   -7.459mA   -5.409mA
-890.9mV  -3.044mA   -4.945mA   -2.555mA
-854.5mV  -1.543mA   -3.208mA   -1.031mA
-818.2mV  -697.7uA   -1.955mA   -355.9uA
-781.8mV  -297uA     -1.088mA   -131.4uA
-745.5mV  -127.2uA   -553uA     -72.75uA
-600mV    -20.9uA    -31.39uA   -24.57uA
1.764V    4.465nA    5.008nA    4.772nA
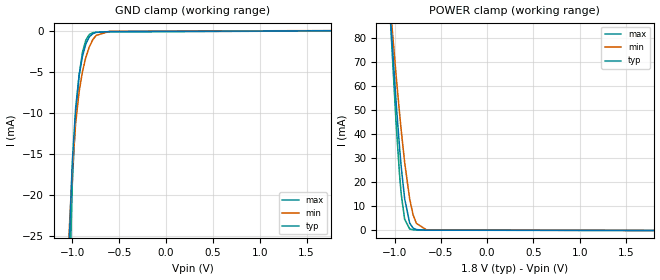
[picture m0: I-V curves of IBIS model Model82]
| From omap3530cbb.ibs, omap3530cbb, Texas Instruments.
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| Model based on original model for IQ0101CS_7LM
|   Sub model IQ0101CS_7LM_PU_ON_1P8
[model]   Model82
|[Input Load]   PU
|[Output Drive]
|Voltage   1.8V
|Mode   INPUT
Model_type   Input
Polarity   Non-Inverting
Vinl =  0.63
Vinh =  1.17
C_comp   0.4935895p   0.3850681p   0.6261927p
[Model Spec]
Vinl   0.63   0.567   0.6615
Vinh   1.17   1.053   1.2285
[Temperature Range]   25   125   -40
[Voltage Range]   1.8   1.62   1.89
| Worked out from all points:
|   GND clamp passes 1 mA (typ) near -0.83 V on its own axis
|   POWER clamp passes 1 mA (typ) near -0.80 V on its own axis
[POWER_clamp]
-1.8V     607.9mA    493.5mA    734.7mA
-1.055V   94.78mA    97.3mA     95.11mA
-1.036V   83.8mA     88.72mA    81.5mA
-981.8mV  52.72mA    63.99mA    43.74mA
-945.5mV  34.39mA    48.68mA    23.03mA
-927.3mV  26.31mA    41.49mA    14.91mA
-890.9mV  13.23mA    28.37mA    4.686mA
-836.4mV  3.084mA    13.09mA    630.5uA
-800mV    992.8uA    6.569mA    265uA
-763.6mV  370.5uA    2.941mA    193.1uA
-654.5mV  119.9uA    238.8uA    151.9uA
1.8V      4.491nA    2.046nA    7.48nA
[GND_clamp]
-1.8V     -542.2mA   -381.9mA   -758.2mA
-1.036V   -27.01mA   -25.18mA   -34.06mA
-1V       -16.07mA   -17.03mA   -18.74mA
-963.6mV  -9.368mA   -11.28mA   -10.22mA
-927.3mV  -5.475mA   -7.472mA   -5.462mA
-890.9mV  -3.09mA    -4.96mA    -2.626mA
-854.5mV  -1.597mA   -3.226mA   -1.125mA
-818.2mV  -761.9uA   -1.975mA   -466.9uA
-781.8mV  -369.9uA   -1.111mA   -249.7uA
-745.5mV  -205.5uA   -580.1uA   -193.5uA
-600mV    -107.5uA   -68.36uA   -154.9uA
1.764V    -5.55uA    13.94uA    -26.17uA
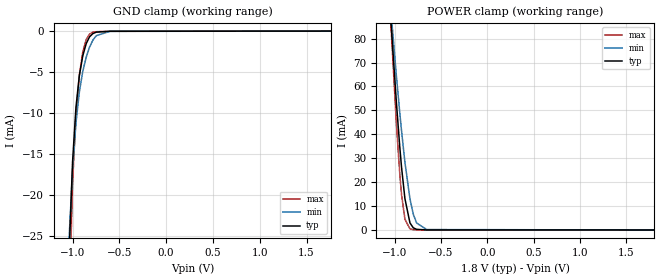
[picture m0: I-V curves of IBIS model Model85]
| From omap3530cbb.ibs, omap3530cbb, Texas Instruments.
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| Model based on original model for IQ0120CS_7LM
|   Sub model 0120CS_PD_PU_OFF_1P8
[model]   Model85
|[Input Load]   PI
|[Output Drive]
|Voltage   1.8V
|Mode   INPUT
Model_type   Input
Polarity   Non-Inverting
Vinl =  0.63
Vinh =  1.17
C_comp   0.4946683p   0.3869884p   0.6246171p
[Model Spec]
Vinl   0.63   0.567   0.6615
Vinh   1.17   1.053   1.2285
[Temperature Range]   25   125   -40
[Voltage Range]   1.8   1.62   1.89
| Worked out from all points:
|   GND clamp passes 1 mA (typ) near -0.83 V on its own axis
|   POWER clamp passes 1 mA (typ) near -0.80 V on its own axis
[POWER_clamp]
-1.8V     607.9mA    493.5mA    734.7mA
-1.055V   94.73mA    97.28mA    95mA
-1.036V   83.75mA    88.7mA     81.38mA
-981.8mV  52.65mA    63.97mA    43.59mA
-945.5mV  34.3mA     48.65mA    22.88mA
-927.3mV  26.21mA    41.46mA    14.76mA
-890.9mV  13.12mA    28.34mA    4.525mA
-836.4mV  2.969mA    13.05mA    471uA
-800mV    877uA      6.518mA    108.6uA
-763.6mV  256.6uA    2.883mA    40.42uA
-654.5mV  16.53uA    170.8uA    12.9uA
1.8V      5.568nA    2.517nA    9.209nA
[GND_clamp]
-1.8V     -542.2mA   -381.9mA   -758.2mA
-1.036V   -26.98mA   -25.17mA   -34.04mA
-1V       -16.04mA   -17.02mA   -18.71mA
-963.6mV  -9.335mA   -11.27mA   -10.18mA
-927.3mV  -5.438mA   -7.459mA   -5.411mA
-890.9mV  -3.045mA   -4.945mA   -2.557mA
-854.5mV  -1.544mA   -3.208mA   -1.034mA
-818.2mV  -698.7uA   -1.955mA   -358.8uA
-781.8mV  -298.1uA   -1.088mA   -134.2uA
-745.5mV  -128.3uA   -553.3uA   -75.31uA
-600mV    -21.47uA   -31.61uA   -25.75uA
1.764V    4.669nA    5.236nA    5.09nA
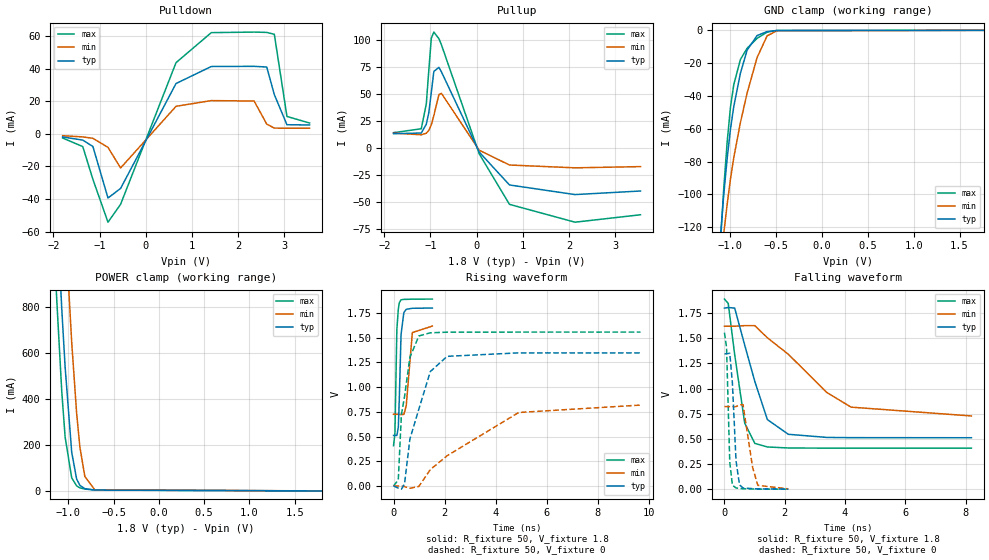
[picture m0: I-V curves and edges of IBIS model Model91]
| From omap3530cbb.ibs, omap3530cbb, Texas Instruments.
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| Model based on original model for BQ0254CS_7LM
|   Sub model 0254CS_PD_PU_OFF_1P8
[model]   Model91
|[Input Load]   PI
|[Output Drive]
|Voltage   1.8V
|Mode   I/O
Model_type   I/O
Polarity   Non-Inverting
Enable   Active-Low
Vinl =  0.63
Vinh =  1.17
Cref =  15.0000pF
Rref =  100.0000M
Vref =  0V
Vmeas =  0.9
C_comp   0.8807545p   0.75692p   1.037524p
[Model Spec]
Vinl   0.63   0.567   0.6615
Vinh   1.17   1.053   1.2285
[Temperature Range]   25   125   -40
[Voltage Range]   1.8   1.62   1.89
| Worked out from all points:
|   slope of the pulldown table from 0 to 0.27 V, typ, clamps not added: 18.2 ohm
|   slope of the pullup table from 0 to 0.27 V, typ, clamps not added: 15.1 ohm
|   GND clamp passes 1 mA (typ) near -0.62 V on its own axis
|   POWER clamp passes 1 mA (typ) near -0.57 V on its own axis
|   rising waveform, R_fixture 50, V_fixture 1.8: 20-80 % time 81.2ps typ, 138ps min, 65.1ps max; typ from 0.511 V to 1.8 V
|   rising waveform, R_fixture 50, V_fixture 0: 20-80 % time 779ps typ, 2.51ns min, 383ps max; typ from 0 V to 1.35 V
|   falling waveform, R_fixture 50, V_fixture 1.8: 20-80 % time 756ps typ, 1.97ns min, 421ps max; typ from 1.8 V to 0.511 V
|   falling waveform, R_fixture 50, V_fixture 0: 20-80 % time 126ps typ, 248ps min, 81.1ps max; typ from 1.35 V to 0.001 V
[POWER_clamp]
-1.8V     7.03A      7.477A     6.772A
-1.182V   1.672A     2.34A      1.267A
-1.164V   1.518A     2.189A     1.114A
-1.127V   1.216A     1.889A     820.4mA
-1.073V   791.2mA    1.448A     431.2mA
-1.036V   538.2mA    1.164A     234.5mA
-963.6mV  168.9mA    647.7mA    57.17mA
-909.1mV  51.94mA    338.6mA    22mA
-872.7mV  24.12mA    189.8mA    13.24mA
-818.2mV  9.796mA    62.59mA    8.394mA
-709.1mV  3.779mA    4.968mA    3.659mA
1.8V      5.391nA    3.441nA    8.971nA
[Pulldown]
-1.8V     -1.896mA   -1.14mA    -2.549mA
-1.364V   -3.858mA   -1.868mA   -7.811mA
-1.145V   -7.758mA   -2.749mA   -27.9mA
-818.2mV  -39.37mA   -8.28mA    -54.21mA
-545.5mV  -33.5mA    -20.95mA   -43.25mA
654.5mV   30.89mA    16.9mA     43.69mA
1.418V    41.32mA    20.41mA    62.11mA
2.345V    41.43mA    20.12mA    62.44mA
2.618V    40.99mA    5.968mA    62.24mA
2.782V    24.07mA    3.525mA    61.09mA
3.055V    5.586mA    3.449mA    10.68mA
3.545V    5.467mA    3.446mA    6.63mA
[Pullup]
-1.8V     13mA       13.47mA    13.94mA
-1.2V     13.58mA    11.97mA    17.52mA
-1.091V   21.69mA    13.4mA     40.44mA
-1.036V   32.56mA    16.02mA    72.05mA
-981.8mV  51.54mA    21.35mA    101.5mA
-927.3mV  70.65mA    29.72mA    107.1mA
-818.2mV  74.4mA     49.19mA    101mA
-763.6mV  70.3mA     50.34mA    95.36mA
54.55mV   -4.056mA   -2.362mA   -5.695mA
709.1mV   -34.52mA   -16.04mA   -52.48mA
2.127V    -43.43mA   -18.65mA   -69.01mA
3.545V    -40.12mA   -17.52mA   -62.13mA
[GND_clamp]
-1.8V     -750.6mA   -623.3mA   -941.3mA
-1.109V   -125.7mA   -143.5mA   -129.8mA
-1.073V   -100.3mA   -123.9mA   -96.46mA
-1.036V   -78.28mA   -106.2mA   -68.22mA
-1V       -60.33mA   -90.75mA   -47.08mA
-963.6mV  -46.48mA   -77.6mA    -33.12mA
-890.9mV  -26.13mA   -56.16mA   -17.76mA
-818.2mV  -12.14mA   -38.32mA   -10.94mA
-709.1mV  -3.177mA   -16.6mA    -4.873mA
-600mV    -740.6uA   -3.353mA   -1.096mA
-490.9mV  -93.6uA    -272.6uA   -80.84uA
1.764V    4.431nA    31.01nA    4.817nA
[Ramp]
dV/dt_f  0.7825339/0.7624452n  0.5427707/2.006602n   0.9042432/0.4261038n
dV/dt_r  0.8347242/0.7803061n  0.5087486/2.537082n   0.9675738/0.3831438n
R_load = 50
[Rising Waveform]
R_fixture = 50
V_fixture = 1.8
V_fixture_min = 1.62
V_fixture_max = 1.89
0s        511.5mV    724.7mV    407.9mV
54ps      511.4mV    724.7mV    525.8mV
130ps     510.5mV    725mV      1.58V
188ps     593mV      725.2mV    1.789V
228ps     897.7mV    724.8mV    1.854V
294ps     1.53V      722.3mV    1.882V
406ps     1.755V     724.1mV    1.887V
498ps     1.786V     812.9mV    1.887V
738ps     1.797V     1.551V     1.889V
1.522ns   1.799V     1.617V     1.89V
[Rising Waveform]
R_fixture = 50
V_fixture = 0
V_fixture_min = 0
V_fixture_max = 0
0s        196.3nV    87.52nV    426.7nV
186ps     -21.54mV   150.4uV    62.06mV
308ps     -32.09mV   229.7uV    721.9mV
430ps     20.87mV    -6.276mV   901.7mV
642ps     475.2mV    -22.79mV   1.302V
994ps     778.2mV    -4.309mV   1.517V
1.442ns   1.157V     165.8mV    1.549V
2.102ns   1.311V     306.4mV    1.555V
4.908ns   1.346V     743.1mV    1.556V
9.682ns   1.346V     818.1mV    1.556V
[Falling Waveform]
R_fixture = 50
V_fixture = 1.8
V_fixture_min = 1.62
V_fixture_max = 1.89
0s        1.8V       1.62V      1.89V
126ps     1.806V     1.62V      1.846V
340ps     1.8V       1.62V      1.336V
674ps     1.43V      1.626V     654.5mV
1.008ns   1.07V      1.626V     455.2mV
1.424ns   691.8mV    1.505V     419.8mV
2.12ns    545.5mV    1.341V     409.5mV
3.398ns   514.5mV    960.7mV    408mV
4.2ns     512.2mV    815.5mV    407.9mV
8.19ns    511.5mV    727.9mV    407.9mV
[Falling Waveform]
R_fixture = 50
V_fixture = 0
V_fixture_min = 0
V_fixture_max = 0
0s        1.346V     821.4mV    1.556V
70ps      1.346V     821.4mV    1.409V
176ps     1.351V     820.6mV    269.6mV
264ps     1.057V     820mV      40.52mV
384ps     281mV      820.9mV    11.98mV
500ps     42.54mV    839.2mV    7.932mV
616ps     12.73mV    840.7mV    3.796mV
934ps     5.076mV    216.6mV    1.629mV
1.108ns   2.908mV    38.08mV    1.152mV
2.12ns    860.2uV    3.249mV    144.3uV
